VERSION 5.8 ;
BUSBITCHARS "[]" ;
DIVIDERCHAR "/" ;
UNITS
    DATABASE MICRONS 1000 ;
END UNITS

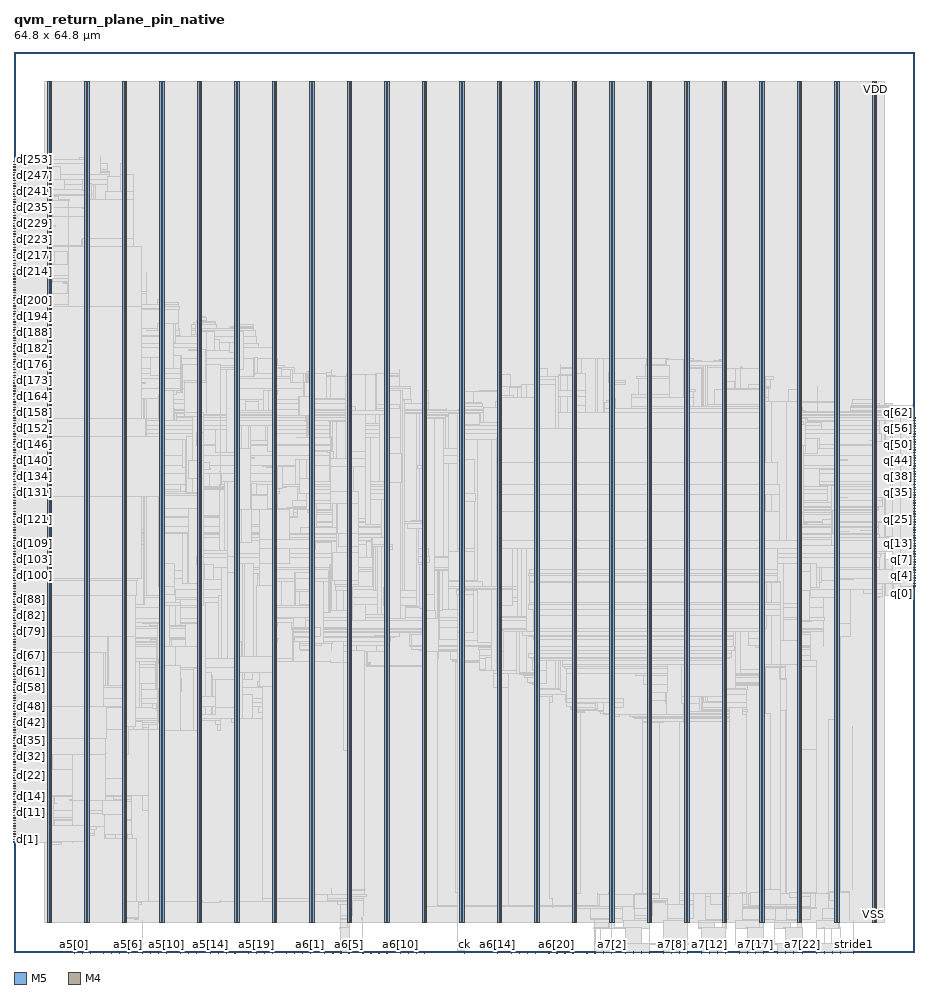
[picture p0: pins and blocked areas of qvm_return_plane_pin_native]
MACRO qvm_return_plane_pin_native
  FOREIGN qvm_return_plane_pin_native 0 0 ;
  CLASS BLOCK ;
  SIZE 64.8 BY 64.8 ;
  PIN a5[0]
    DIRECTION INPUT ;
    USE SIGNAL ;
    PORT
      LAYER M5 ;
        RECT  4.32 -0.072 4.344 0.072 ;
    END
  END a5[0]
  PIN a5[10]
    DIRECTION INPUT ;
    USE SIGNAL ;
    PORT
      LAYER M5 ;
        RECT  10.944 -0.072 10.968 0.072 ;
    END
  END a5[10]
  PIN a5[11]
    DIRECTION INPUT ;
    USE SIGNAL ;
    PORT
      LAYER M5 ;
        RECT  11.952 -0.072 11.976 0.072 ;
    END
  END a5[11]
  PIN a5[12]
    DIRECTION INPUT ;
    USE SIGNAL ;
    PORT
      LAYER M5 ;
        RECT  12.528 -0.072 12.552 0.072 ;
    END
  END a5[12]
  PIN a5[13]
    DIRECTION INPUT ;
    USE SIGNAL ;
    PORT
      LAYER M5 ;
        RECT  13.104 -0.072 13.128 0.072 ;
    END
  END a5[13]
  PIN a5[14]
    DIRECTION INPUT ;
    USE SIGNAL ;
    PORT
      LAYER M5 ;
        RECT  14.112 -0.072 14.136 0.072 ;
    END
  END a5[14]
  PIN a5[15]
    DIRECTION INPUT ;
    USE SIGNAL ;
    PORT
      LAYER M5 ;
        RECT  14.688 -0.072 14.712 0.072 ;
    END
  END a5[15]
  PIN a5[16]
    DIRECTION INPUT ;
    USE SIGNAL ;
    PORT
      LAYER M5 ;
        RECT  15.264 -0.072 15.288 0.072 ;
    END
  END a5[16]
  PIN a5[17]
    DIRECTION INPUT ;
    USE SIGNAL ;
    PORT
      LAYER M5 ;
        RECT  15.888 -0.072 15.912 0.072 ;
    END
  END a5[17]
  PIN a5[18]
    DIRECTION INPUT ;
    USE SIGNAL ;
    PORT
      LAYER M5 ;
        RECT  16.848 -0.072 16.872 0.072 ;
    END
  END a5[18]
  PIN a5[19]
    DIRECTION INPUT ;
    USE SIGNAL ;
    PORT
      LAYER M5 ;
        RECT  17.424 -0.072 17.448 0.072 ;
    END
  END a5[19]
  PIN a5[1]
    DIRECTION INPUT ;
    USE SIGNAL ;
    PORT
      LAYER M5 ;
        RECT  4.896 -0.072 4.92 0.072 ;
    END
  END a5[1]
  PIN a5[20]
    DIRECTION INPUT ;
    USE SIGNAL ;
    PORT
      LAYER M5 ;
        RECT  18 -0.072 18.024 0.072 ;
    END
  END a5[20]
  PIN a5[21]
    DIRECTION INPUT ;
    USE SIGNAL ;
    PORT
      LAYER M5 ;
        RECT  18.576 -0.072 18.6 0.072 ;
    END
  END a5[21]
  PIN a5[22]
    DIRECTION INPUT ;
    USE SIGNAL ;
    PORT
      LAYER M5 ;
        RECT  19.584 -0.072 19.608 0.072 ;
    END
  END a5[22]
  PIN a5[23]
    DIRECTION INPUT ;
    USE SIGNAL ;
    PORT
      LAYER M5 ;
        RECT  20.16 -0.072 20.184 0.072 ;
    END
  END a5[23]
  PIN a5[2]
    DIRECTION INPUT ;
    USE SIGNAL ;
    PORT
      LAYER M5 ;
        RECT  5.472 -0.072 5.496 0.072 ;
    END
  END a5[2]
  PIN a5[3]
    DIRECTION INPUT ;
    USE SIGNAL ;
    PORT
      LAYER M5 ;
        RECT  6.432 -0.072 6.456 0.072 ;
    END
  END a5[3]
  PIN a5[4]
    DIRECTION INPUT ;
    USE SIGNAL ;
    PORT
      LAYER M5 ;
        RECT  7.008 -0.072 7.032 0.072 ;
    END
  END a5[4]
  PIN a5[5]
    DIRECTION INPUT ;
    USE SIGNAL ;
    PORT
      LAYER M5 ;
        RECT  7.584 -0.072 7.608 0.072 ;
    END
  END a5[5]
  PIN a5[6]
    DIRECTION INPUT ;
    USE SIGNAL ;
    PORT
      LAYER M5 ;
        RECT  8.208 -0.072 8.232 0.072 ;
    END
  END a5[6]
  PIN a5[7]
    DIRECTION INPUT ;
    USE SIGNAL ;
    PORT
      LAYER M5 ;
        RECT  9.216 -0.072 9.24 0.072 ;
    END
  END a5[7]
  PIN a5[8]
    DIRECTION INPUT ;
    USE SIGNAL ;
    PORT
      LAYER M5 ;
        RECT  9.792 -0.072 9.816 0.072 ;
    END
  END a5[8]
  PIN a5[9]
    DIRECTION INPUT ;
    USE SIGNAL ;
    PORT
      LAYER M5 ;
        RECT  10.368 -0.072 10.392 0.072 ;
    END
  END a5[9]
  PIN a6[0]
    DIRECTION INPUT ;
    USE SIGNAL ;
    PORT
      LAYER M5 ;
        RECT  20.736 -0.072 20.76 0.072 ;
    END
  END a6[0]
  PIN a6[10]
    DIRECTION INPUT ;
    USE SIGNAL ;
    PORT
      LAYER M5 ;
        RECT  27.792 -0.072 27.816 0.072 ;
    END
  END a6[10]
  PIN a6[11]
    DIRECTION INPUT ;
    USE SIGNAL ;
    PORT
      LAYER M5 ;
        RECT  28.368 -0.072 28.392 0.072 ;
    END
  END a6[11]
  PIN a6[12]
    DIRECTION INPUT ;
    USE SIGNAL ;
    PORT
      LAYER M5 ;
        RECT  28.944 -0.072 28.968 0.072 ;
    END
  END a6[12]
  PIN a6[13]
    DIRECTION INPUT ;
    USE SIGNAL ;
    PORT
      LAYER M5 ;
        RECT  29.52 -0.072 29.544 0.072 ;
    END
  END a6[13]
  PIN a6[14]
    DIRECTION INPUT ;
    USE SIGNAL ;
    PORT
      LAYER M5 ;
        RECT  34.8 -0.072 34.824 0.072 ;
    END
  END a6[14]
  PIN a6[15]
    DIRECTION INPUT ;
    USE SIGNAL ;
    PORT
      LAYER M5 ;
        RECT  35.808 -0.072 35.832 0.072 ;
    END
  END a6[15]
  PIN a6[16]
    DIRECTION INPUT ;
    USE SIGNAL ;
    PORT
      LAYER M5 ;
        RECT  36.384 -0.072 36.408 0.072 ;
    END
  END a6[16]
  PIN a6[17]
    DIRECTION INPUT ;
    USE SIGNAL ;
    PORT
      LAYER M5 ;
        RECT  36.96 -0.072 36.984 0.072 ;
    END
  END a6[17]
  PIN a6[18]
    DIRECTION INPUT ;
    USE SIGNAL ;
    PORT
      LAYER M5 ;
        RECT  37.536 -0.072 37.56 0.072 ;
    END
  END a6[18]
  PIN a6[19]
    DIRECTION INPUT ;
    USE SIGNAL ;
    PORT
      LAYER M5 ;
        RECT  38.496 -0.072 38.52 0.072 ;
    END
  END a6[19]
  PIN a6[1]
    DIRECTION INPUT ;
    USE SIGNAL ;
    PORT
      LAYER M5 ;
        RECT  21.312 -0.072 21.336 0.072 ;
    END
  END a6[1]
  PIN a6[20]
    DIRECTION INPUT ;
    USE SIGNAL ;
    PORT
      LAYER M5 ;
        RECT  39.072 -0.072 39.096 0.072 ;
    END
  END a6[20]
  PIN a6[21]
    DIRECTION INPUT ;
    USE SIGNAL ;
    PORT
      LAYER M5 ;
        RECT  39.648 -0.072 39.672 0.072 ;
    END
  END a6[21]
  PIN a6[22]
    DIRECTION INPUT ;
    USE SIGNAL ;
    PORT
      LAYER M5 ;
        RECT  40.224 -0.072 40.248 0.072 ;
    END
  END a6[22]
  PIN a6[23]
    DIRECTION INPUT ;
    USE SIGNAL ;
    PORT
      LAYER M5 ;
        RECT  41.232 -0.072 41.256 0.072 ;
    END
  END a6[23]
  PIN a6[2]
    DIRECTION INPUT ;
    USE SIGNAL ;
    PORT
      LAYER M5 ;
        RECT  22.32 -0.072 22.344 0.072 ;
    END
  END a6[2]
  PIN a6[3]
    DIRECTION INPUT ;
    USE SIGNAL ;
    PORT
      LAYER M5 ;
        RECT  22.944 -0.072 22.968 0.072 ;
    END
  END a6[3]
  PIN a6[4]
    DIRECTION INPUT ;
    USE SIGNAL ;
    PORT
      LAYER M5 ;
        RECT  23.52 -0.072 23.544 0.072 ;
    END
  END a6[4]
  PIN a6[5]
    DIRECTION INPUT ;
    USE SIGNAL ;
    PORT
      LAYER M5 ;
        RECT  24.096 -0.072 24.12 0.072 ;
    END
  END a6[5]
  PIN a6[6]
    DIRECTION INPUT ;
    USE SIGNAL ;
    PORT
      LAYER M5 ;
        RECT  25.104 -0.072 25.128 0.072 ;
    END
  END a6[6]
  PIN a6[7]
    DIRECTION INPUT ;
    USE SIGNAL ;
    PORT
      LAYER M5 ;
        RECT  25.68 -0.072 25.704 0.072 ;
    END
  END a6[7]
  PIN a6[8]
    DIRECTION INPUT ;
    USE SIGNAL ;
    PORT
      LAYER M5 ;
        RECT  26.256 -0.072 26.28 0.072 ;
    END
  END a6[8]
  PIN a6[9]
    DIRECTION INPUT ;
    USE SIGNAL ;
    PORT
      LAYER M5 ;
        RECT  26.832 -0.072 26.856 0.072 ;
    END
  END a6[9]
  PIN a7[0]
    DIRECTION INPUT ;
    USE SIGNAL ;
    PORT
      LAYER M5 ;
        RECT  41.808 -0.072 41.832 0.072 ;
    END
  END a7[0]
  PIN a7[10]
    DIRECTION INPUT ;
    USE SIGNAL ;
    PORT
      LAYER M5 ;
        RECT  48.48 -0.072 48.504 0.072 ;
    END
  END a7[10]
  PIN a7[11]
    DIRECTION INPUT ;
    USE SIGNAL ;
    PORT
      LAYER M5 ;
        RECT  49.488 -0.072 49.512 0.072 ;
    END
  END a7[11]
  PIN a7[12]
    DIRECTION INPUT ;
    USE SIGNAL ;
    PORT
      LAYER M5 ;
        RECT  50.064 -0.072 50.088 0.072 ;
    END
  END a7[12]
  PIN a7[13]
    DIRECTION INPUT ;
    USE SIGNAL ;
    PORT
      LAYER M5 ;
        RECT  50.64 -0.072 50.664 0.072 ;
    END
  END a7[13]
  PIN a7[14]
    DIRECTION INPUT ;
    USE SIGNAL ;
    PORT
      LAYER M5 ;
        RECT  51.216 -0.072 51.24 0.072 ;
    END
  END a7[14]
  PIN a7[15]
    DIRECTION INPUT ;
    USE SIGNAL ;
    PORT
      LAYER M5 ;
        RECT  52.224 -0.072 52.248 0.072 ;
    END
  END a7[15]
  PIN a7[16]
    DIRECTION INPUT ;
    USE SIGNAL ;
    PORT
      LAYER M5 ;
        RECT  52.8 -0.072 52.824 0.072 ;
    END
  END a7[16]
  PIN a7[17]
    DIRECTION INPUT ;
    USE SIGNAL ;
    PORT
      LAYER M5 ;
        RECT  53.376 -0.072 53.4 0.072 ;
    END
  END a7[17]
  PIN a7[18]
    DIRECTION INPUT ;
    USE SIGNAL ;
    PORT
      LAYER M5 ;
        RECT  53.952 -0.072 53.976 0.072 ;
    END
  END a7[18]
  PIN a7[19]
    DIRECTION INPUT ;
    USE SIGNAL ;
    PORT
      LAYER M5 ;
        RECT  54.96 -0.072 54.984 0.072 ;
    END
  END a7[19]
  PIN a7[1]
    DIRECTION INPUT ;
    USE SIGNAL ;
    PORT
      LAYER M5 ;
        RECT  42.432 -0.072 42.456 0.072 ;
    END
  END a7[1]
  PIN a7[20]
    DIRECTION INPUT ;
    USE SIGNAL ;
    PORT
      LAYER M5 ;
        RECT  55.536 -0.072 55.56 0.072 ;
    END
  END a7[20]
  PIN a7[21]
    DIRECTION INPUT ;
    USE SIGNAL ;
    PORT
      LAYER M5 ;
        RECT  56.112 -0.072 56.136 0.072 ;
    END
  END a7[21]
  PIN a7[22]
    DIRECTION INPUT ;
    USE SIGNAL ;
    PORT
      LAYER M5 ;
        RECT  56.736 -0.072 56.76 0.072 ;
    END
  END a7[22]
  PIN a7[23]
    DIRECTION INPUT ;
    USE SIGNAL ;
    PORT
      LAYER M5 ;
        RECT  57.744 -0.072 57.768 0.072 ;
    END
  END a7[23]
  PIN a7[2]
    DIRECTION INPUT ;
    USE SIGNAL ;
    PORT
      LAYER M5 ;
        RECT  43.008 -0.072 43.032 0.072 ;
    END
  END a7[2]
  PIN a7[3]
    DIRECTION INPUT ;
    USE SIGNAL ;
    PORT
      LAYER M5 ;
        RECT  44.016 -0.072 44.04 0.072 ;
    END
  END a7[3]
  PIN a7[4]
    DIRECTION INPUT ;
    USE SIGNAL ;
    PORT
      LAYER M5 ;
        RECT  44.592 -0.072 44.616 0.072 ;
    END
  END a7[4]
  PIN a7[5]
    DIRECTION INPUT ;
    USE SIGNAL ;
    PORT
      LAYER M5 ;
        RECT  45.168 -0.072 45.192 0.072 ;
    END
  END a7[5]
  PIN a7[6]
    DIRECTION INPUT ;
    USE SIGNAL ;
    PORT
      LAYER M5 ;
        RECT  45.744 -0.072 45.768 0.072 ;
    END
  END a7[6]
  PIN a7[7]
    DIRECTION INPUT ;
    USE SIGNAL ;
    PORT
      LAYER M5 ;
        RECT  46.752 -0.072 46.776 0.072 ;
    END
  END a7[7]
  PIN a7[8]
    DIRECTION INPUT ;
    USE SIGNAL ;
    PORT
      LAYER M5 ;
        RECT  47.328 -0.072 47.352 0.072 ;
    END
  END a7[8]
  PIN a7[9]
    DIRECTION INPUT ;
    USE SIGNAL ;
    PORT
      LAYER M5 ;
        RECT  47.904 -0.072 47.928 0.072 ;
    END
  END a7[9]
  PIN ck
    DIRECTION INPUT ;
    USE SIGNAL ;
    PORT
      LAYER M5 ;
        RECT  32.4 -0.072 32.424 0.072 ;
    END
  END ck
  PIN d[0]
    DIRECTION INPUT ;
    USE SIGNAL ;
    PORT
      LAYER M4 ;
        RECT  -0.072 7.92 0.072 7.944 ;
    END
  END d[0]
  PIN d[100]
    DIRECTION INPUT ;
    USE SIGNAL ;
    PORT
      LAYER M4 ;
        RECT  -0.072 27.12 0.072 27.144 ;
    END
  END d[100]
  PIN d[101]
    DIRECTION INPUT ;
    USE SIGNAL ;
    PORT
      LAYER M4 ;
        RECT  -0.072 27.312 0.072 27.336 ;
    END
  END d[101]
  PIN d[102]
    DIRECTION INPUT ;
    USE SIGNAL ;
    PORT
      LAYER M4 ;
        RECT  -0.072 27.504 0.072 27.528 ;
    END
  END d[102]
  PIN d[103]
    DIRECTION INPUT ;
    USE SIGNAL ;
    PORT
      LAYER M4 ;
        RECT  -0.072 27.696 0.072 27.72 ;
    END
  END d[103]
  PIN d[104]
    DIRECTION INPUT ;
    USE SIGNAL ;
    PORT
      LAYER M4 ;
        RECT  -0.072 27.888 0.072 27.912 ;
    END
  END d[104]
  PIN d[105]
    DIRECTION INPUT ;
    USE SIGNAL ;
    PORT
      LAYER M4 ;
        RECT  -0.072 28.08 0.072 28.104 ;
    END
  END d[105]
  PIN d[106]
    DIRECTION INPUT ;
    USE SIGNAL ;
    PORT
      LAYER M4 ;
        RECT  -0.072 28.272 0.072 28.296 ;
    END
  END d[106]
  PIN d[107]
    DIRECTION INPUT ;
    USE SIGNAL ;
    PORT
      LAYER M4 ;
        RECT  -0.072 28.464 0.072 28.488 ;
    END
  END d[107]
  PIN d[108]
    DIRECTION INPUT ;
    USE SIGNAL ;
    PORT
      LAYER M4 ;
        RECT  -0.072 28.656 0.072 28.68 ;
    END
  END d[108]
  PIN d[109]
    DIRECTION INPUT ;
    USE SIGNAL ;
    PORT
      LAYER M4 ;
        RECT  -0.072 28.848 0.072 28.872 ;
    END
  END d[109]
  PIN d[10]
    DIRECTION INPUT ;
    USE SIGNAL ;
    PORT
      LAYER M4 ;
        RECT  -0.072 9.84 0.072 9.864 ;
    END
  END d[10]
  PIN d[110]
    DIRECTION INPUT ;
    USE SIGNAL ;
    PORT
      LAYER M4 ;
        RECT  -0.072 29.04 0.072 29.064 ;
    END
  END d[110]
  PIN d[111]
    DIRECTION INPUT ;
    USE SIGNAL ;
    PORT
      LAYER M4 ;
        RECT  -0.072 29.232 0.072 29.256 ;
    END
  END d[111]
  PIN d[112]
    DIRECTION INPUT ;
    USE SIGNAL ;
    PORT
      LAYER M4 ;
        RECT  -0.072 29.424 0.072 29.448 ;
    END
  END d[112]
  PIN d[113]
    DIRECTION INPUT ;
    USE SIGNAL ;
    PORT
      LAYER M4 ;
        RECT  -0.072 29.616 0.072 29.64 ;
    END
  END d[113]
  PIN d[114]
    DIRECTION INPUT ;
    USE SIGNAL ;
    PORT
      LAYER M4 ;
        RECT  -0.072 29.808 0.072 29.832 ;
    END
  END d[114]
  PIN d[115]
    DIRECTION INPUT ;
    USE SIGNAL ;
    PORT
      LAYER M4 ;
        RECT  -0.072 30 0.072 30.024 ;
    END
  END d[115]
  PIN d[116]
    DIRECTION INPUT ;
    USE SIGNAL ;
    PORT
      LAYER M4 ;
        RECT  -0.072 30.192 0.072 30.216 ;
    END
  END d[116]
  PIN d[117]
    DIRECTION INPUT ;
    USE SIGNAL ;
    PORT
      LAYER M4 ;
        RECT  -0.072 30.384 0.072 30.408 ;
    END
  END d[117]
  PIN d[118]
    DIRECTION INPUT ;
    USE SIGNAL ;
    PORT
      LAYER M4 ;
        RECT  -0.072 30.576 0.072 30.6 ;
    END
  END d[118]
  PIN d[119]
    DIRECTION INPUT ;
    USE SIGNAL ;
    PORT
      LAYER M4 ;
        RECT  -0.072 30.768 0.072 30.792 ;
    END
  END d[119]
  PIN d[11]
    DIRECTION INPUT ;
    USE SIGNAL ;
    PORT
      LAYER M4 ;
        RECT  -0.072 10.032 0.072 10.056 ;
    END
  END d[11]
  PIN d[120]
    DIRECTION INPUT ;
    USE SIGNAL ;
    PORT
      LAYER M4 ;
        RECT  -0.072 30.96 0.072 30.984 ;
    END
  END d[120]
  PIN d[121]
    DIRECTION INPUT ;
    USE SIGNAL ;
    PORT
      LAYER M4 ;
        RECT  -0.072 31.152 0.072 31.176 ;
    END
  END d[121]
  PIN d[122]
    DIRECTION INPUT ;
    USE SIGNAL ;
    PORT
      LAYER M4 ;
        RECT  -0.072 31.344 0.072 31.368 ;
    END
  END d[122]
  PIN d[123]
    DIRECTION INPUT ;
    USE SIGNAL ;
    PORT
      LAYER M4 ;
        RECT  -0.072 31.536 0.072 31.56 ;
    END
  END d[123]
  PIN d[124]
    DIRECTION INPUT ;
    USE SIGNAL ;
    PORT
      LAYER M4 ;
        RECT  -0.072 31.728 0.072 31.752 ;
    END
  END d[124]
  PIN d[125]
    DIRECTION INPUT ;
    USE SIGNAL ;
    PORT
      LAYER M4 ;
        RECT  -0.072 31.92 0.072 31.944 ;
    END
  END d[125]
  PIN d[126]
    DIRECTION INPUT ;
    USE SIGNAL ;
    PORT
      LAYER M4 ;
        RECT  -0.072 32.112 0.072 32.136 ;
    END
  END d[126]
  PIN d[127]
    DIRECTION INPUT ;
    USE SIGNAL ;
    PORT
      LAYER M4 ;
        RECT  -0.072 32.304 0.072 32.328 ;
    END
  END d[127]
  PIN d[128]
    DIRECTION INPUT ;
    USE SIGNAL ;
    PORT
      LAYER M4 ;
        RECT  -0.072 32.496 0.072 32.52 ;
    END
  END d[128]
  PIN d[129]
    DIRECTION INPUT ;
    USE SIGNAL ;
    PORT
      LAYER M4 ;
        RECT  -0.072 32.688 0.072 32.712 ;
    END
  END d[129]
  PIN d[12]
    DIRECTION INPUT ;
    USE SIGNAL ;
    PORT
      LAYER M4 ;
        RECT  -0.072 10.224 0.072 10.248 ;
    END
  END d[12]
  PIN d[130]
    DIRECTION INPUT ;
    USE SIGNAL ;
    PORT
      LAYER M4 ;
        RECT  -0.072 32.88 0.072 32.904 ;
    END
  END d[130]
  PIN d[131]
    DIRECTION INPUT ;
    USE SIGNAL ;
    PORT
      LAYER M4 ;
        RECT  -0.072 33.072 0.072 33.096 ;
    END
  END d[131]
  PIN d[132]
    DIRECTION INPUT ;
    USE SIGNAL ;
    PORT
      LAYER M4 ;
        RECT  -0.072 33.264 0.072 33.288 ;
    END
  END d[132]
  PIN d[133]
    DIRECTION INPUT ;
    USE SIGNAL ;
    PORT
      LAYER M4 ;
        RECT  -0.072 33.456 0.072 33.48 ;
    END
  END d[133]
  PIN d[134]
    DIRECTION INPUT ;
    USE SIGNAL ;
    PORT
      LAYER M4 ;
        RECT  -0.072 33.648 0.072 33.672 ;
    END
  END d[134]
  PIN d[135]
    DIRECTION INPUT ;
    USE SIGNAL ;
    PORT
      LAYER M4 ;
        RECT  -0.072 33.84 0.072 33.864 ;
    END
  END d[135]
  PIN d[136]
    DIRECTION INPUT ;
    USE SIGNAL ;
    PORT
      LAYER M4 ;
        RECT  -0.072 34.032 0.072 34.056 ;
    END
  END d[136]
  PIN d[137]
    DIRECTION INPUT ;
    USE SIGNAL ;
    PORT
      LAYER M4 ;
        RECT  -0.072 34.224 0.072 34.248 ;
    END
  END d[137]
  PIN d[138]
    DIRECTION INPUT ;
    USE SIGNAL ;
    PORT
      LAYER M4 ;
        RECT  -0.072 34.416 0.072 34.44 ;
    END
  END d[138]
  PIN d[139]
    DIRECTION INPUT ;
    USE SIGNAL ;
    PORT
      LAYER M4 ;
        RECT  -0.072 34.608 0.072 34.632 ;
    END
  END d[139]
  PIN d[13]
    DIRECTION INPUT ;
    USE SIGNAL ;
    PORT
      LAYER M4 ;
        RECT  -0.072 10.416 0.072 10.44 ;
    END
  END d[13]
  PIN d[140]
    DIRECTION INPUT ;
    USE SIGNAL ;
    PORT
      LAYER M4 ;
        RECT  -0.072 34.8 0.072 34.824 ;
    END
  END d[140]
  PIN d[141]
    DIRECTION INPUT ;
    USE SIGNAL ;
    PORT
      LAYER M4 ;
        RECT  -0.072 34.992 0.072 35.016 ;
    END
  END d[141]
  PIN d[142]
    DIRECTION INPUT ;
    USE SIGNAL ;
    PORT
      LAYER M4 ;
        RECT  -0.072 35.184 0.072 35.208 ;
    END
  END d[142]
  PIN d[143]
    DIRECTION INPUT ;
    USE SIGNAL ;
    PORT
      LAYER M4 ;
        RECT  -0.072 35.376 0.072 35.4 ;
    END
  END d[143]
  PIN d[144]
    DIRECTION INPUT ;
    USE SIGNAL ;
    PORT
      LAYER M4 ;
        RECT  -0.072 35.568 0.072 35.592 ;
    END
  END d[144]
  PIN d[145]
    DIRECTION INPUT ;
    USE SIGNAL ;
    PORT
      LAYER M4 ;
        RECT  -0.072 35.76 0.072 35.784 ;
    END
  END d[145]
  PIN d[146]
    DIRECTION INPUT ;
    USE SIGNAL ;
    PORT
      LAYER M4 ;
        RECT  -0.072 35.952 0.072 35.976 ;
    END
  END d[146]
  PIN d[147]
    DIRECTION INPUT ;
    USE SIGNAL ;
    PORT
      LAYER M4 ;
        RECT  -0.072 36.144 0.072 36.168 ;
    END
  END d[147]
  PIN d[148]
    DIRECTION INPUT ;
    USE SIGNAL ;
    PORT
      LAYER M4 ;
        RECT  -0.072 36.336 0.072 36.36 ;
    END
  END d[148]
  PIN d[149]
    DIRECTION INPUT ;
    USE SIGNAL ;
    PORT
      LAYER M4 ;
        RECT  -0.072 36.528 0.072 36.552 ;
    END
  END d[149]
  PIN d[14]
    DIRECTION INPUT ;
    USE SIGNAL ;
    PORT
      LAYER M4 ;
        RECT  -0.072 10.608 0.072 10.632 ;
    END
  END d[14]
  PIN d[150]
    DIRECTION INPUT ;
    USE SIGNAL ;
    PORT
      LAYER M4 ;
        RECT  -0.072 36.72 0.072 36.744 ;
    END
  END d[150]
  PIN d[151]
    DIRECTION INPUT ;
    USE SIGNAL ;
    PORT
      LAYER M4 ;
        RECT  -0.072 36.912 0.072 36.936 ;
    END
  END d[151]
  PIN d[152]
    DIRECTION INPUT ;
    USE SIGNAL ;
    PORT
      LAYER M4 ;
        RECT  -0.072 37.104 0.072 37.128 ;
    END
  END d[152]
  PIN d[153]
    DIRECTION INPUT ;
    USE SIGNAL ;
    PORT
      LAYER M4 ;
        RECT  -0.072 37.296 0.072 37.32 ;
    END
  END d[153]
  PIN d[154]
    DIRECTION INPUT ;
    USE SIGNAL ;
    PORT
      LAYER M4 ;
        RECT  -0.072 37.488 0.072 37.512 ;
    END
  END d[154]
  PIN d[155]
    DIRECTION INPUT ;
    USE SIGNAL ;
    PORT
      LAYER M4 ;
        RECT  -0.072 37.68 0.072 37.704 ;
    END
  END d[155]
  PIN d[156]
    DIRECTION INPUT ;
    USE SIGNAL ;
    PORT
      LAYER M4 ;
        RECT  -0.072 37.872 0.072 37.896 ;
    END
  END d[156]
  PIN d[157]
    DIRECTION INPUT ;
    USE SIGNAL ;
    PORT
      LAYER M4 ;
        RECT  -0.072 38.064 0.072 38.088 ;
    END
  END d[157]
  PIN d[158]
    DIRECTION INPUT ;
    USE SIGNAL ;
    PORT
      LAYER M4 ;
        RECT  -0.072 38.256 0.072 38.28 ;
    END
  END d[158]
  PIN d[159]
    DIRECTION INPUT ;
    USE SIGNAL ;
    PORT
      LAYER M4 ;
        RECT  -0.072 38.448 0.072 38.472 ;
    END
  END d[159]
  PIN d[15]
    DIRECTION INPUT ;
    USE SIGNAL ;
    PORT
      LAYER M4 ;
        RECT  -0.072 10.8 0.072 10.824 ;
    END
  END d[15]
  PIN d[160]
    DIRECTION INPUT ;
    USE SIGNAL ;
    PORT
      LAYER M4 ;
        RECT  -0.072 38.64 0.072 38.664 ;
    END
  END d[160]
  PIN d[161]
    DIRECTION INPUT ;
    USE SIGNAL ;
    PORT
      LAYER M4 ;
        RECT  -0.072 38.832 0.072 38.856 ;
    END
  END d[161]
  PIN d[162]
    DIRECTION INPUT ;
    USE SIGNAL ;
    PORT
      LAYER M4 ;
        RECT  -0.072 39.024 0.072 39.048 ;
    END
  END d[162]
  PIN d[163]
    DIRECTION INPUT ;
    USE SIGNAL ;
    PORT
      LAYER M4 ;
        RECT  -0.072 39.216 0.072 39.24 ;
    END
  END d[163]
  PIN d[164]
    DIRECTION INPUT ;
    USE SIGNAL ;
    PORT
      LAYER M4 ;
        RECT  -0.072 39.408 0.072 39.432 ;
    END
  END d[164]
  PIN d[165]
    DIRECTION INPUT ;
    USE SIGNAL ;
    PORT
      LAYER M4 ;
        RECT  -0.072 39.6 0.072 39.624 ;
    END
  END d[165]
  PIN d[166]
    DIRECTION INPUT ;
    USE SIGNAL ;
    PORT
      LAYER M4 ;
        RECT  -0.072 39.792 0.072 39.816 ;
    END
  END d[166]
  PIN d[167]
    DIRECTION INPUT ;
    USE SIGNAL ;
    PORT
      LAYER M4 ;
        RECT  -0.072 39.984 0.072 40.008 ;
    END
  END d[167]
  PIN d[168]
    DIRECTION INPUT ;
    USE SIGNAL ;
    PORT
      LAYER M4 ;
        RECT  -0.072 40.176 0.072 40.2 ;
    END
  END d[168]
  PIN d[169]
    DIRECTION INPUT ;
    USE SIGNAL ;
    PORT
      LAYER M4 ;
        RECT  -0.072 40.368 0.072 40.392 ;
    END
  END d[169]
  PIN d[16]
    DIRECTION INPUT ;
    USE SIGNAL ;
    PORT
      LAYER M4 ;
        RECT  -0.072 10.992 0.072 11.016 ;
    END
  END d[16]
  PIN d[170]
    DIRECTION INPUT ;
    USE SIGNAL ;
    PORT
      LAYER M4 ;
        RECT  -0.072 40.56 0.072 40.584 ;
    END
  END d[170]
  PIN d[171]
    DIRECTION INPUT ;
    USE SIGNAL ;
    PORT
      LAYER M4 ;
        RECT  -0.072 40.752 0.072 40.776 ;
    END
  END d[171]
  PIN d[172]
    DIRECTION INPUT ;
    USE SIGNAL ;
    PORT
      LAYER M4 ;
        RECT  -0.072 40.944 0.072 40.968 ;
    END
  END d[172]
  PIN d[173]
    DIRECTION INPUT ;
    USE SIGNAL ;
    PORT
      LAYER M4 ;
        RECT  -0.072 41.136 0.072 41.16 ;
    END
  END d[173]
  PIN d[174]
    DIRECTION INPUT ;
    USE SIGNAL ;
    PORT
      LAYER M4 ;
        RECT  -0.072 41.328 0.072 41.352 ;
    END
  END d[174]
  PIN d[175]
    DIRECTION INPUT ;
    USE SIGNAL ;
    PORT
      LAYER M4 ;
        RECT  -0.072 41.52 0.072 41.544 ;
    END
  END d[175]
  PIN d[176]
    DIRECTION INPUT ;
    USE SIGNAL ;
    PORT
      LAYER M4 ;
        RECT  -0.072 41.712 0.072 41.736 ;
    END
  END d[176]
  PIN d[177]
    DIRECTION INPUT ;
    USE SIGNAL ;
    PORT
      LAYER M4 ;
        RECT  -0.072 41.904 0.072 41.928 ;
    END
  END d[177]
  PIN d[178]
    DIRECTION INPUT ;
    USE SIGNAL ;
    PORT
      LAYER M4 ;
        RECT  -0.072 42.096 0.072 42.12 ;
    END
  END d[178]
  PIN d[179]
    DIRECTION INPUT ;
    USE SIGNAL ;
    PORT
      LAYER M4 ;
        RECT  -0.072 42.288 0.072 42.312 ;
    END
  END d[179]
  PIN d[17]
    DIRECTION INPUT ;
    USE SIGNAL ;
    PORT
      LAYER M4 ;
        RECT  -0.072 11.184 0.072 11.208 ;
    END
  END d[17]
  PIN d[180]
    DIRECTION INPUT ;
    USE SIGNAL ;
    PORT
      LAYER M4 ;
        RECT  -0.072 42.48 0.072 42.504 ;
    END
  END d[180]
  PIN d[181]
    DIRECTION INPUT ;
    USE SIGNAL ;
    PORT
      LAYER M4 ;
        RECT  -0.072 42.672 0.072 42.696 ;
    END
  END d[181]
  PIN d[182]
    DIRECTION INPUT ;
    USE SIGNAL ;
    PORT
      LAYER M4 ;
        RECT  -0.072 42.864 0.072 42.888 ;
    END
  END d[182]
  PIN d[183]
    DIRECTION INPUT ;
    USE SIGNAL ;
    PORT
      LAYER M4 ;
        RECT  -0.072 43.056 0.072 43.08 ;
    END
  END d[183]
  PIN d[184]
    DIRECTION INPUT ;
    USE SIGNAL ;
    PORT
      LAYER M4 ;
        RECT  -0.072 43.248 0.072 43.272 ;
    END
  END d[184]
  PIN d[185]
    DIRECTION INPUT ;
    USE SIGNAL ;
    PORT
      LAYER M4 ;
        RECT  -0.072 43.44 0.072 43.464 ;
    END
  END d[185]
  PIN d[186]
    DIRECTION INPUT ;
    USE SIGNAL ;
    PORT
      LAYER M4 ;
        RECT  -0.072 43.632 0.072 43.656 ;
    END
  END d[186]
  PIN d[187]
    DIRECTION INPUT ;
    USE SIGNAL ;
    PORT
      LAYER M4 ;
        RECT  -0.072 43.824 0.072 43.848 ;
    END
  END d[187]
  PIN d[188]
    DIRECTION INPUT ;
    USE SIGNAL ;
    PORT
      LAYER M4 ;
        RECT  -0.072 44.016 0.072 44.04 ;
    END
  END d[188]
  PIN d[189]
    DIRECTION INPUT ;
    USE SIGNAL ;
    PORT
      LAYER M4 ;
        RECT  -0.072 44.208 0.072 44.232 ;
    END
  END d[189]
  PIN d[18]
    DIRECTION INPUT ;
    USE SIGNAL ;
    PORT
      LAYER M4 ;
        RECT  -0.072 11.376 0.072 11.4 ;
    END
  END d[18]
  PIN d[190]
    DIRECTION INPUT ;
    USE SIGNAL ;
    PORT
      LAYER M4 ;
        RECT  -0.072 44.4 0.072 44.424 ;
    END
  END d[190]
  PIN d[191]
    DIRECTION INPUT ;
    USE SIGNAL ;
    PORT
      LAYER M4 ;
        RECT  -0.072 44.592 0.072 44.616 ;
    END
  END d[191]
  PIN d[192]
    DIRECTION INPUT ;
    USE SIGNAL ;
    PORT
      LAYER M4 ;
        RECT  -0.072 44.784 0.072 44.808 ;
    END
  END d[192]
  PIN d[193]
    DIRECTION INPUT ;
    USE SIGNAL ;
    PORT
      LAYER M4 ;
        RECT  -0.072 44.976 0.072 45 ;
    END
  END d[193]
  PIN d[194]
    DIRECTION INPUT ;
    USE SIGNAL ;
    PORT
      LAYER M4 ;
        RECT  -0.072 45.168 0.072 45.192 ;
    END
  END d[194]
  PIN d[195]
    DIRECTION INPUT ;
    USE SIGNAL ;
    PORT
      LAYER M4 ;
        RECT  -0.072 45.36 0.072 45.384 ;
    END
  END d[195]
  PIN d[196]
    DIRECTION INPUT ;
    USE SIGNAL ;
    PORT
      LAYER M4 ;
        RECT  -0.072 45.552 0.072 45.576 ;
    END
  END d[196]
  PIN d[197]
    DIRECTION INPUT ;
    USE SIGNAL ;
    PORT
      LAYER M4 ;
        RECT  -0.072 45.744 0.072 45.768 ;
    END
  END d[197]
  PIN d[198]
    DIRECTION INPUT ;
    USE SIGNAL ;
    PORT
      LAYER M4 ;
        RECT  -0.072 45.936 0.072 45.96 ;
    END
  END d[198]
  PIN d[199]
    DIRECTION INPUT ;
    USE SIGNAL ;
    PORT
      LAYER M4 ;
        RECT  -0.072 46.128 0.072 46.152 ;
    END
  END d[199]
  PIN d[19]
    DIRECTION INPUT ;
    USE SIGNAL ;
    PORT
      LAYER M4 ;
        RECT  -0.072 11.568 0.072 11.592 ;
    END
  END d[19]
  PIN d[1]
    DIRECTION INPUT ;
    USE SIGNAL ;
    PORT
      LAYER M4 ;
        RECT  -0.072 8.112 0.072 8.136 ;
    END
  END d[1]
  PIN d[200]
    DIRECTION INPUT ;
    USE SIGNAL ;
    PORT
      LAYER M4 ;
        RECT  -0.072 46.32 0.072 46.344 ;
    END
  END d[200]
  PIN d[201]
    DIRECTION INPUT ;
    USE SIGNAL ;
    PORT
      LAYER M4 ;
        RECT  -0.072 46.512 0.072 46.536 ;
    END
  END d[201]
  PIN d[202]
    DIRECTION INPUT ;
    USE SIGNAL ;
    PORT
      LAYER M4 ;
        RECT  -0.072 46.704 0.072 46.728 ;
    END
  END d[202]
  PIN d[203]
    DIRECTION INPUT ;
    USE SIGNAL ;
    PORT
      LAYER M4 ;
        RECT  -0.072 46.896 0.072 46.92 ;
    END
  END d[203]
  PIN d[204]
    DIRECTION INPUT ;
    USE SIGNAL ;
    PORT
      LAYER M4 ;
        RECT  -0.072 47.088 0.072 47.112 ;
    END
  END d[204]
  PIN d[205]
    DIRECTION INPUT ;
    USE SIGNAL ;
    PORT
      LAYER M4 ;
        RECT  -0.072 47.28 0.072 47.304 ;
    END
  END d[205]
  PIN d[206]
    DIRECTION INPUT ;
    USE SIGNAL ;
    PORT
      LAYER M4 ;
        RECT  -0.072 47.472 0.072 47.496 ;
    END
  END d[206]
  PIN d[207]
    DIRECTION INPUT ;
    USE SIGNAL ;
    PORT
      LAYER M4 ;
        RECT  -0.072 47.664 0.072 47.688 ;
    END
  END d[207]
  PIN d[208]
    DIRECTION INPUT ;
    USE SIGNAL ;
    PORT
      LAYER M4 ;
        RECT  -0.072 47.856 0.072 47.88 ;
    END
  END d[208]
  PIN d[209]
    DIRECTION INPUT ;
    USE SIGNAL ;
    PORT
      LAYER M4 ;
        RECT  -0.072 48.048 0.072 48.072 ;
    END
  END d[209]
  PIN d[20]
    DIRECTION INPUT ;
    USE SIGNAL ;
    PORT
      LAYER M4 ;
        RECT  -0.072 11.76 0.072 11.784 ;
    END
  END d[20]
  PIN d[210]
    DIRECTION INPUT ;
    USE SIGNAL ;
    PORT
      LAYER M4 ;
        RECT  -0.072 48.24 0.072 48.264 ;
    END
  END d[210]
  PIN d[211]
    DIRECTION INPUT ;
    USE SIGNAL ;
    PORT
      LAYER M4 ;
        RECT  -0.072 48.432 0.072 48.456 ;
    END
  END d[211]
  PIN d[212]
    DIRECTION INPUT ;
    USE SIGNAL ;
    PORT
      LAYER M4 ;
        RECT  -0.072 48.624 0.072 48.648 ;
    END
  END d[212]
  PIN d[213]
    DIRECTION INPUT ;
    USE SIGNAL ;
    PORT
      LAYER M4 ;
        RECT  -0.072 48.816 0.072 48.84 ;
    END
  END d[213]
  PIN d[214]
    DIRECTION INPUT ;
    USE SIGNAL ;
    PORT
      LAYER M4 ;
        RECT  -0.072 49.008 0.072 49.032 ;
    END
  END d[214]
  PIN d[215]
    DIRECTION INPUT ;
    USE SIGNAL ;
    PORT
      LAYER M4 ;
        RECT  -0.072 49.2 0.072 49.224 ;
    END
  END d[215]
  PIN d[216]
    DIRECTION INPUT ;
    USE SIGNAL ;
    PORT
      LAYER M4 ;
        RECT  -0.072 49.392 0.072 49.416 ;
    END
  END d[216]
  PIN d[217]
    DIRECTION INPUT ;
    USE SIGNAL ;
    PORT
      LAYER M4 ;
        RECT  -0.072 49.584 0.072 49.608 ;
    END
  END d[217]
  PIN d[218]
    DIRECTION INPUT ;
    USE SIGNAL ;
    PORT
      LAYER M4 ;
        RECT  -0.072 49.776 0.072 49.8 ;
    END
  END d[218]
  PIN d[219]
    DIRECTION INPUT ;
    USE SIGNAL ;
    PORT
      LAYER M4 ;
        RECT  -0.072 49.968 0.072 49.992 ;
    END
  END d[219]
  PIN d[21]
    DIRECTION INPUT ;
    USE SIGNAL ;
    PORT
      LAYER M4 ;
        RECT  -0.072 11.952 0.072 11.976 ;
    END
  END d[21]
  PIN d[220]
    DIRECTION INPUT ;
    USE SIGNAL ;
    PORT
      LAYER M4 ;
        RECT  -0.072 50.16 0.072 50.184 ;
    END
  END d[220]
  PIN d[221]
    DIRECTION INPUT ;
    USE SIGNAL ;
    PORT
      LAYER M4 ;
        RECT  -0.072 50.352 0.072 50.376 ;
    END
  END d[221]
  PIN d[222]
    DIRECTION INPUT ;
    USE SIGNAL ;
    PORT
      LAYER M4 ;
        RECT  -0.072 50.544 0.072 50.568 ;
    END
  END d[222]
  PIN d[223]
    DIRECTION INPUT ;
    USE SIGNAL ;
    PORT
      LAYER M4 ;
        RECT  -0.072 50.736 0.072 50.76 ;
    END
  END d[223]
  PIN d[224]
    DIRECTION INPUT ;
    USE SIGNAL ;
    PORT
      LAYER M4 ;
        RECT  -0.072 50.928 0.072 50.952 ;
    END
  END d[224]
  PIN d[225]
    DIRECTION INPUT ;
    USE SIGNAL ;
    PORT
      LAYER M4 ;
        RECT  -0.072 51.12 0.072 51.144 ;
    END
  END d[225]
  PIN d[226]
    DIRECTION INPUT ;
    USE SIGNAL ;
    PORT
      LAYER M4 ;
        RECT  -0.072 51.312 0.072 51.336 ;
    END
  END d[226]
  PIN d[227]
    DIRECTION INPUT ;
    USE SIGNAL ;
    PORT
      LAYER M4 ;
        RECT  -0.072 51.504 0.072 51.528 ;
    END
  END d[227]
  PIN d[228]
    DIRECTION INPUT ;
    USE SIGNAL ;
    PORT
      LAYER M4 ;
        RECT  -0.072 51.696 0.072 51.72 ;
    END
  END d[228]
  PIN d[229]
    DIRECTION INPUT ;
    USE SIGNAL ;
    PORT
      LAYER M4 ;
        RECT  -0.072 51.888 0.072 51.912 ;
    END
  END d[229]
  PIN d[22]
    DIRECTION INPUT ;
    USE SIGNAL ;
    PORT
      LAYER M4 ;
        RECT  -0.072 12.144 0.072 12.168 ;
    END
  END d[22]
  PIN d[230]
    DIRECTION INPUT ;
    USE SIGNAL ;
    PORT
      LAYER M4 ;
        RECT  -0.072 52.08 0.072 52.104 ;
    END
  END d[230]
  PIN d[231]
    DIRECTION INPUT ;
    USE SIGNAL ;
    PORT
      LAYER M4 ;
        RECT  -0.072 52.272 0.072 52.296 ;
    END
  END d[231]
  PIN d[232]
    DIRECTION INPUT ;
    USE SIGNAL ;
    PORT
      LAYER M4 ;
        RECT  -0.072 52.464 0.072 52.488 ;
    END
  END d[232]
  PIN d[233]
    DIRECTION INPUT ;
    USE SIGNAL ;
    PORT
      LAYER M4 ;
        RECT  -0.072 52.656 0.072 52.68 ;
    END
  END d[233]
  PIN d[234]
    DIRECTION INPUT ;
    USE SIGNAL ;
    PORT
      LAYER M4 ;
        RECT  -0.072 52.848 0.072 52.872 ;
    END
  END d[234]
  PIN d[235]
    DIRECTION INPUT ;
    USE SIGNAL ;
    PORT
      LAYER M4 ;
        RECT  -0.072 53.04 0.072 53.064 ;
    END
  END d[235]
  PIN d[236]
    DIRECTION INPUT ;
    USE SIGNAL ;
    PORT
      LAYER M4 ;
        RECT  -0.072 53.232 0.072 53.256 ;
    END
  END d[236]
  PIN d[237]
    DIRECTION INPUT ;
    USE SIGNAL ;
    PORT
      LAYER M4 ;
        RECT  -0.072 53.424 0.072 53.448 ;
    END
  END d[237]
  PIN d[238]
    DIRECTION INPUT ;
    USE SIGNAL ;
    PORT
      LAYER M4 ;
        RECT  -0.072 53.616 0.072 53.64 ;
    END
  END d[238]
  PIN d[239]
    DIRECTION INPUT ;
    USE SIGNAL ;
    PORT
      LAYER M4 ;
        RECT  -0.072 53.808 0.072 53.832 ;
    END
  END d[239]
  PIN d[23]
    DIRECTION INPUT ;
    USE SIGNAL ;
    PORT
      LAYER M4 ;
        RECT  -0.072 12.336 0.072 12.36 ;
    END
  END d[23]
  PIN d[240]
    DIRECTION INPUT ;
    USE SIGNAL ;
    PORT
      LAYER M4 ;
        RECT  -0.072 54 0.072 54.024 ;
    END
  END d[240]
  PIN d[241]
    DIRECTION INPUT ;
    USE SIGNAL ;
    PORT
      LAYER M4 ;
        RECT  -0.072 54.192 0.072 54.216 ;
    END
  END d[241]
  PIN d[242]
    DIRECTION INPUT ;
    USE SIGNAL ;
    PORT
      LAYER M4 ;
        RECT  -0.072 54.384 0.072 54.408 ;
    END
  END d[242]
  PIN d[243]
    DIRECTION INPUT ;
    USE SIGNAL ;
    PORT
      LAYER M4 ;
        RECT  -0.072 54.576 0.072 54.6 ;
    END
  END d[243]
  PIN d[244]
    DIRECTION INPUT ;
    USE SIGNAL ;
    PORT
      LAYER M4 ;
        RECT  -0.072 54.768 0.072 54.792 ;
    END
  END d[244]
  PIN d[245]
    DIRECTION INPUT ;
    USE SIGNAL ;
    PORT
      LAYER M4 ;
        RECT  -0.072 54.96 0.072 54.984 ;
    END
  END d[245]
  PIN d[246]
    DIRECTION INPUT ;
    USE SIGNAL ;
    PORT
      LAYER M4 ;
        RECT  -0.072 55.152 0.072 55.176 ;
    END
  END d[246]
  PIN d[247]
    DIRECTION INPUT ;
    USE SIGNAL ;
    PORT
      LAYER M4 ;
        RECT  -0.072 55.344 0.072 55.368 ;
    END
  END d[247]
  PIN d[248]
    DIRECTION INPUT ;
    USE SIGNAL ;
    PORT
      LAYER M4 ;
        RECT  -0.072 55.536 0.072 55.56 ;
    END
  END d[248]
  PIN d[249]
    DIRECTION INPUT ;
    USE SIGNAL ;
    PORT
      LAYER M4 ;
        RECT  -0.072 55.728 0.072 55.752 ;
    END
  END d[249]
  PIN d[24]
    DIRECTION INPUT ;
    USE SIGNAL ;
    PORT
      LAYER M4 ;
        RECT  -0.072 12.528 0.072 12.552 ;
    END
  END d[24]
  PIN d[250]
    DIRECTION INPUT ;
    USE SIGNAL ;
    PORT
      LAYER M4 ;
        RECT  -0.072 55.92 0.072 55.944 ;
    END
  END d[250]
  PIN d[251]
    DIRECTION INPUT ;
    USE SIGNAL ;
    PORT
      LAYER M4 ;
        RECT  -0.072 56.112 0.072 56.136 ;
    END
  END d[251]
  PIN d[252]
    DIRECTION INPUT ;
    USE SIGNAL ;
    PORT
      LAYER M4 ;
        RECT  -0.072 56.304 0.072 56.328 ;
    END
  END d[252]
  PIN d[253]
    DIRECTION INPUT ;
    USE SIGNAL ;
    PORT
      LAYER M4 ;
        RECT  -0.072 56.496 0.072 56.52 ;
    END
  END d[253]
  PIN d[254]
    DIRECTION INPUT ;
    USE SIGNAL ;
    PORT
      LAYER M4 ;
        RECT  -0.072 56.688 0.072 56.712 ;
    END
  END d[254]
  PIN d[255]
    DIRECTION INPUT ;
    USE SIGNAL ;
    PORT
      LAYER M4 ;
        RECT  -0.072 56.88 0.072 56.904 ;
    END
  END d[255]
  PIN d[25]
    DIRECTION INPUT ;
    USE SIGNAL ;
    PORT
      LAYER M4 ;
        RECT  -0.072 12.72 0.072 12.744 ;
    END
  END d[25]
  PIN d[26]
    DIRECTION INPUT ;
    USE SIGNAL ;
    PORT
      LAYER M4 ;
        RECT  -0.072 12.912 0.072 12.936 ;
    END
  END d[26]
  PIN d[27]
    DIRECTION INPUT ;
    USE SIGNAL ;
    PORT
      LAYER M4 ;
        RECT  -0.072 13.104 0.072 13.128 ;
    END
  END d[27]
  PIN d[28]
    DIRECTION INPUT ;
    USE SIGNAL ;
    PORT
      LAYER M4 ;
        RECT  -0.072 13.296 0.072 13.32 ;
    END
  END d[28]
  PIN d[29]
    DIRECTION INPUT ;
    USE SIGNAL ;
    PORT
      LAYER M4 ;
        RECT  -0.072 13.488 0.072 13.512 ;
    END
  END d[29]
  PIN d[2]
    DIRECTION INPUT ;
    USE SIGNAL ;
    PORT
      LAYER M4 ;
        RECT  -0.072 8.304 0.072 8.328 ;
    END
  END d[2]
  PIN d[30]
    DIRECTION INPUT ;
    USE SIGNAL ;
    PORT
      LAYER M4 ;
        RECT  -0.072 13.68 0.072 13.704 ;
    END
  END d[30]
  PIN d[31]
    DIRECTION INPUT ;
    USE SIGNAL ;
    PORT
      LAYER M4 ;
        RECT  -0.072 13.872 0.072 13.896 ;
    END
  END d[31]
  PIN d[32]
    DIRECTION INPUT ;
    USE SIGNAL ;
    PORT
      LAYER M4 ;
        RECT  -0.072 14.064 0.072 14.088 ;
    END
  END d[32]
  PIN d[33]
    DIRECTION INPUT ;
    USE SIGNAL ;
    PORT
      LAYER M4 ;
        RECT  -0.072 14.256 0.072 14.28 ;
    END
  END d[33]
  PIN d[34]
    DIRECTION INPUT ;
    USE SIGNAL ;
    PORT
      LAYER M4 ;
        RECT  -0.072 14.448 0.072 14.472 ;
    END
  END d[34]
  PIN d[35]
    DIRECTION INPUT ;
    USE SIGNAL ;
    PORT
      LAYER M4 ;
        RECT  -0.072 14.64 0.072 14.664 ;
    END
  END d[35]
  PIN d[36]
    DIRECTION INPUT ;
    USE SIGNAL ;
    PORT
      LAYER M4 ;
        RECT  -0.072 14.832 0.072 14.856 ;
    END
  END d[36]
  PIN d[37]
    DIRECTION INPUT ;
    USE SIGNAL ;
    PORT
      LAYER M4 ;
        RECT  -0.072 15.024 0.072 15.048 ;
    END
  END d[37]
  PIN d[38]
    DIRECTION INPUT ;
    USE SIGNAL ;
    PORT
      LAYER M4 ;
        RECT  -0.072 15.216 0.072 15.24 ;
    END
  END d[38]
  PIN d[39]
    DIRECTION INPUT ;
    USE SIGNAL ;
    PORT
      LAYER M4 ;
        RECT  -0.072 15.408 0.072 15.432 ;
    END
  END d[39]
  PIN d[3]
    DIRECTION INPUT ;
    USE SIGNAL ;
    PORT
      LAYER M4 ;
        RECT  -0.072 8.496 0.072 8.52 ;
    END
  END d[3]
  PIN d[40]
    DIRECTION INPUT ;
    USE SIGNAL ;
    PORT
      LAYER M4 ;
        RECT  -0.072 15.6 0.072 15.624 ;
    END
  END d[40]
  PIN d[41]
    DIRECTION INPUT ;
    USE SIGNAL ;
    PORT
      LAYER M4 ;
        RECT  -0.072 15.792 0.072 15.816 ;
    END
  END d[41]
  PIN d[42]
    DIRECTION INPUT ;
    USE SIGNAL ;
    PORT
      LAYER M4 ;
        RECT  -0.072 15.984 0.072 16.008 ;
    END
  END d[42]
  PIN d[43]
    DIRECTION INPUT ;
    USE SIGNAL ;
    PORT
      LAYER M4 ;
        RECT  -0.072 16.176 0.072 16.2 ;
    END
  END d[43]
  PIN d[44]
    DIRECTION INPUT ;
    USE SIGNAL ;
    PORT
      LAYER M4 ;
        RECT  -0.072 16.368 0.072 16.392 ;
    END
  END d[44]
  PIN d[45]
    DIRECTION INPUT ;
    USE SIGNAL ;
    PORT
      LAYER M4 ;
        RECT  -0.072 16.56 0.072 16.584 ;
    END
  END d[45]
  PIN d[46]
    DIRECTION INPUT ;
    USE SIGNAL ;
    PORT
      LAYER M4 ;
        RECT  -0.072 16.752 0.072 16.776 ;
    END
  END d[46]
  PIN d[47]
    DIRECTION INPUT ;
    USE SIGNAL ;
    PORT
      LAYER M4 ;
        RECT  -0.072 16.944 0.072 16.968 ;
    END
  END d[47]
  PIN d[48]
    DIRECTION INPUT ;
    USE SIGNAL ;
    PORT
      LAYER M4 ;
        RECT  -0.072 17.136 0.072 17.16 ;
    END
  END d[48]
  PIN d[49]
    DIRECTION INPUT ;
    USE SIGNAL ;
    PORT
      LAYER M4 ;
        RECT  -0.072 17.328 0.072 17.352 ;
    END
  END d[49]
  PIN d[4]
    DIRECTION INPUT ;
    USE SIGNAL ;
    PORT
      LAYER M4 ;
        RECT  -0.072 8.688 0.072 8.712 ;
    END
  END d[4]
  PIN d[50]
    DIRECTION INPUT ;
    USE SIGNAL ;
    PORT
      LAYER M4 ;
        RECT  -0.072 17.52 0.072 17.544 ;
    END
  END d[50]
  PIN d[51]
    DIRECTION INPUT ;
    USE SIGNAL ;
    PORT
      LAYER M4 ;
        RECT  -0.072 17.712 0.072 17.736 ;
    END
  END d[51]
  PIN d[52]
    DIRECTION INPUT ;
    USE SIGNAL ;
    PORT
      LAYER M4 ;
        RECT  -0.072 17.904 0.072 17.928 ;
    END
  END d[52]
  PIN d[53]
    DIRECTION INPUT ;
    USE SIGNAL ;
    PORT
      LAYER M4 ;
        RECT  -0.072 18.096 0.072 18.12 ;
    END
  END d[53]
  PIN d[54]
    DIRECTION INPUT ;
    USE SIGNAL ;
    PORT
      LAYER M4 ;
        RECT  -0.072 18.288 0.072 18.312 ;
    END
  END d[54]
  PIN d[55]
    DIRECTION INPUT ;
    USE SIGNAL ;
    PORT
      LAYER M4 ;
        RECT  -0.072 18.48 0.072 18.504 ;
    END
  END d[55]
  PIN d[56]
    DIRECTION INPUT ;
    USE SIGNAL ;
    PORT
      LAYER M4 ;
        RECT  -0.072 18.672 0.072 18.696 ;
    END
  END d[56]
  PIN d[57]
    DIRECTION INPUT ;
    USE SIGNAL ;
    PORT
      LAYER M4 ;
        RECT  -0.072 18.864 0.072 18.888 ;
    END
  END d[57]
  PIN d[58]
    DIRECTION INPUT ;
    USE SIGNAL ;
    PORT
      LAYER M4 ;
        RECT  -0.072 19.056 0.072 19.08 ;
    END
  END d[58]
  PIN d[59]
    DIRECTION INPUT ;
    USE SIGNAL ;
    PORT
      LAYER M4 ;
        RECT  -0.072 19.248 0.072 19.272 ;
    END
  END d[59]
  PIN d[5]
    DIRECTION INPUT ;
    USE SIGNAL ;
    PORT
      LAYER M4 ;
        RECT  -0.072 8.88 0.072 8.904 ;
    END
  END d[5]
  PIN d[60]
    DIRECTION INPUT ;
    USE SIGNAL ;
    PORT
      LAYER M4 ;
        RECT  -0.072 19.44 0.072 19.464 ;
    END
  END d[60]
  PIN d[61]
    DIRECTION INPUT ;
    USE SIGNAL ;
    PORT
      LAYER M4 ;
        RECT  -0.072 19.632 0.072 19.656 ;
    END
  END d[61]
  PIN d[62]
    DIRECTION INPUT ;
    USE SIGNAL ;
    PORT
      LAYER M4 ;
        RECT  -0.072 19.824 0.072 19.848 ;
    END
  END d[62]
  PIN d[63]
    DIRECTION INPUT ;
    USE SIGNAL ;
    PORT
      LAYER M4 ;
        RECT  -0.072 20.016 0.072 20.04 ;
    END
  END d[63]
  PIN d[64]
    DIRECTION INPUT ;
    USE SIGNAL ;
    PORT
      LAYER M4 ;
        RECT  -0.072 20.208 0.072 20.232 ;
    END
  END d[64]
  PIN d[65]
    DIRECTION INPUT ;
    USE SIGNAL ;
    PORT
      LAYER M4 ;
        RECT  -0.072 20.4 0.072 20.424 ;
    END
  END d[65]
  PIN d[66]
    DIRECTION INPUT ;
    USE SIGNAL ;
    PORT
      LAYER M4 ;
        RECT  -0.072 20.592 0.072 20.616 ;
    END
  END d[66]
  PIN d[67]
    DIRECTION INPUT ;
    USE SIGNAL ;
    PORT
      LAYER M4 ;
        RECT  -0.072 20.784 0.072 20.808 ;
    END
  END d[67]
  PIN d[68]
    DIRECTION INPUT ;
    USE SIGNAL ;
    PORT
      LAYER M4 ;
        RECT  -0.072 20.976 0.072 21 ;
    END
  END d[68]
  PIN d[69]
    DIRECTION INPUT ;
    USE SIGNAL ;
    PORT
      LAYER M4 ;
        RECT  -0.072 21.168 0.072 21.192 ;
    END
  END d[69]
  PIN d[6]
    DIRECTION INPUT ;
    USE SIGNAL ;
    PORT
      LAYER M4 ;
        RECT  -0.072 9.072 0.072 9.096 ;
    END
  END d[6]
  PIN d[70]
    DIRECTION INPUT ;
    USE SIGNAL ;
    PORT
      LAYER M4 ;
        RECT  -0.072 21.36 0.072 21.384 ;
    END
  END d[70]
  PIN d[71]
    DIRECTION INPUT ;
    USE SIGNAL ;
    PORT
      LAYER M4 ;
        RECT  -0.072 21.552 0.072 21.576 ;
    END
  END d[71]
  PIN d[72]
    DIRECTION INPUT ;
    USE SIGNAL ;
    PORT
      LAYER M4 ;
        RECT  -0.072 21.744 0.072 21.768 ;
    END
  END d[72]
  PIN d[73]
    DIRECTION INPUT ;
    USE SIGNAL ;
    PORT
      LAYER M4 ;
        RECT  -0.072 21.936 0.072 21.96 ;
    END
  END d[73]
  PIN d[74]
    DIRECTION INPUT ;
    USE SIGNAL ;
    PORT
      LAYER M4 ;
        RECT  -0.072 22.128 0.072 22.152 ;
    END
  END d[74]
  PIN d[75]
    DIRECTION INPUT ;
    USE SIGNAL ;
    PORT
      LAYER M4 ;
        RECT  -0.072 22.32 0.072 22.344 ;
    END
  END d[75]
  PIN d[76]
    DIRECTION INPUT ;
    USE SIGNAL ;
    PORT
      LAYER M4 ;
        RECT  -0.072 22.512 0.072 22.536 ;
    END
  END d[76]
  PIN d[77]
    DIRECTION INPUT ;
    USE SIGNAL ;
    PORT
      LAYER M4 ;
        RECT  -0.072 22.704 0.072 22.728 ;
    END
  END d[77]
  PIN d[78]
    DIRECTION INPUT ;
    USE SIGNAL ;
    PORT
      LAYER M4 ;
        RECT  -0.072 22.896 0.072 22.92 ;
    END
  END d[78]
  PIN d[79]
    DIRECTION INPUT ;
    USE SIGNAL ;
    PORT
      LAYER M4 ;
        RECT  -0.072 23.088 0.072 23.112 ;
    END
  END d[79]
  PIN d[7]
    DIRECTION INPUT ;
    USE SIGNAL ;
    PORT
      LAYER M4 ;
        RECT  -0.072 9.264 0.072 9.288 ;
    END
  END d[7]
  PIN d[80]
    DIRECTION INPUT ;
    USE SIGNAL ;
    PORT
      LAYER M4 ;
        RECT  -0.072 23.28 0.072 23.304 ;
    END
  END d[80]
  PIN d[81]
    DIRECTION INPUT ;
    USE SIGNAL ;
    PORT
      LAYER M4 ;
        RECT  -0.072 23.472 0.072 23.496 ;
    END
  END d[81]
  PIN d[82]
    DIRECTION INPUT ;
    USE SIGNAL ;
    PORT
      LAYER M4 ;
        RECT  -0.072 23.664 0.072 23.688 ;
    END
  END d[82]
  PIN d[83]
    DIRECTION INPUT ;
    USE SIGNAL ;
    PORT
      LAYER M4 ;
        RECT  -0.072 23.856 0.072 23.88 ;
    END
  END d[83]
  PIN d[84]
    DIRECTION INPUT ;
    USE SIGNAL ;
    PORT
      LAYER M4 ;
        RECT  -0.072 24.048 0.072 24.072 ;
    END
  END d[84]
  PIN d[85]
    DIRECTION INPUT ;
    USE SIGNAL ;
    PORT
      LAYER M4 ;
        RECT  -0.072 24.24 0.072 24.264 ;
    END
  END d[85]
  PIN d[86]
    DIRECTION INPUT ;
    USE SIGNAL ;
    PORT
      LAYER M4 ;
        RECT  -0.072 24.432 0.072 24.456 ;
    END
  END d[86]
  PIN d[87]
    DIRECTION INPUT ;
    USE SIGNAL ;
    PORT
      LAYER M4 ;
        RECT  -0.072 24.624 0.072 24.648 ;
    END
  END d[87]
  PIN d[88]
    DIRECTION INPUT ;
    USE SIGNAL ;
    PORT
      LAYER M4 ;
        RECT  -0.072 24.816 0.072 24.84 ;
    END
  END d[88]
  PIN d[89]
    DIRECTION INPUT ;
    USE SIGNAL ;
    PORT
      LAYER M4 ;
        RECT  -0.072 25.008 0.072 25.032 ;
    END
  END d[89]
  PIN d[8]
    DIRECTION INPUT ;
    USE SIGNAL ;
    PORT
      LAYER M4 ;
        RECT  -0.072 9.456 0.072 9.48 ;
    END
  END d[8]
  PIN d[90]
    DIRECTION INPUT ;
    USE SIGNAL ;
    PORT
      LAYER M4 ;
        RECT  -0.072 25.2 0.072 25.224 ;
    END
  END d[90]
  PIN d[91]
    DIRECTION INPUT ;
    USE SIGNAL ;
    PORT
      LAYER M4 ;
        RECT  -0.072 25.392 0.072 25.416 ;
    END
  END d[91]
  PIN d[92]
    DIRECTION INPUT ;
    USE SIGNAL ;
    PORT
      LAYER M4 ;
        RECT  -0.072 25.584 0.072 25.608 ;
    END
  END d[92]
  PIN d[93]
    DIRECTION INPUT ;
    USE SIGNAL ;
    PORT
      LAYER M4 ;
        RECT  -0.072 25.776 0.072 25.8 ;
    END
  END d[93]
  PIN d[94]
    DIRECTION INPUT ;
    USE SIGNAL ;
    PORT
      LAYER M4 ;
        RECT  -0.072 25.968 0.072 25.992 ;
    END
  END d[94]
  PIN d[95]
    DIRECTION INPUT ;
    USE SIGNAL ;
    PORT
      LAYER M4 ;
        RECT  -0.072 26.16 0.072 26.184 ;
    END
  END d[95]
  PIN d[96]
    DIRECTION INPUT ;
    USE SIGNAL ;
    PORT
      LAYER M4 ;
        RECT  -0.072 26.352 0.072 26.376 ;
    END
  END d[96]
  PIN d[97]
    DIRECTION INPUT ;
    USE SIGNAL ;
    PORT
      LAYER M4 ;
        RECT  -0.072 26.544 0.072 26.568 ;
    END
  END d[97]
  PIN d[98]
    DIRECTION INPUT ;
    USE SIGNAL ;
    PORT
      LAYER M4 ;
        RECT  -0.072 26.736 0.072 26.76 ;
    END
  END d[98]
  PIN d[99]
    DIRECTION INPUT ;
    USE SIGNAL ;
    PORT
      LAYER M4 ;
        RECT  -0.072 26.928 0.072 26.952 ;
    END
  END d[99]
  PIN d[9]
    DIRECTION INPUT ;
    USE SIGNAL ;
    PORT
      LAYER M4 ;
        RECT  -0.072 9.648 0.072 9.672 ;
    END
  END d[9]
  PIN q[0]
    DIRECTION OUTPUT ;
    USE SIGNAL ;
    PORT
      LAYER M4 ;
        RECT  64.728 26.352 64.872 26.376 ;
    END
  END q[0]
  PIN q[10]
    DIRECTION OUTPUT ;
    USE SIGNAL ;
    PORT
      LAYER M4 ;
        RECT  64.728 28.272 64.872 28.296 ;
    END
  END q[10]
  PIN q[11]
    DIRECTION OUTPUT ;
    USE SIGNAL ;
    PORT
      LAYER M4 ;
        RECT  64.728 28.464 64.872 28.488 ;
    END
  END q[11]
  PIN q[12]
    DIRECTION OUTPUT ;
    USE SIGNAL ;
    PORT
      LAYER M4 ;
        RECT  64.728 28.656 64.872 28.68 ;
    END
  END q[12]
  PIN q[13]
    DIRECTION OUTPUT ;
    USE SIGNAL ;
    PORT
      LAYER M4 ;
        RECT  64.728 28.848 64.872 28.872 ;
    END
  END q[13]
  PIN q[14]
    DIRECTION OUTPUT ;
    USE SIGNAL ;
    PORT
      LAYER M4 ;
        RECT  64.728 29.04 64.872 29.064 ;
    END
  END q[14]
  PIN q[15]
    DIRECTION OUTPUT ;
    USE SIGNAL ;
    PORT
      LAYER M4 ;
        RECT  64.728 29.232 64.872 29.256 ;
    END
  END q[15]
  PIN q[16]
    DIRECTION OUTPUT ;
    USE SIGNAL ;
    PORT
      LAYER M4 ;
        RECT  64.728 29.424 64.872 29.448 ;
    END
  END q[16]
  PIN q[17]
    DIRECTION OUTPUT ;
    USE SIGNAL ;
    PORT
      LAYER M4 ;
        RECT  64.728 29.616 64.872 29.64 ;
    END
  END q[17]
  PIN q[18]
    DIRECTION OUTPUT ;
    USE SIGNAL ;
    PORT
      LAYER M4 ;
        RECT  64.728 29.808 64.872 29.832 ;
    END
  END q[18]
  PIN q[19]
    DIRECTION OUTPUT ;
    USE SIGNAL ;
    PORT
      LAYER M4 ;
        RECT  64.728 30 64.872 30.024 ;
    END
  END q[19]
  PIN q[1]
    DIRECTION OUTPUT ;
    USE SIGNAL ;
    PORT
      LAYER M4 ;
        RECT  64.728 26.544 64.872 26.568 ;
    END
  END q[1]
  PIN q[20]
    DIRECTION OUTPUT ;
    USE SIGNAL ;
    PORT
      LAYER M4 ;
        RECT  64.728 30.192 64.872 30.216 ;
    END
  END q[20]
  PIN q[21]
    DIRECTION OUTPUT ;
    USE SIGNAL ;
    PORT
      LAYER M4 ;
        RECT  64.728 30.384 64.872 30.408 ;
    END
  END q[21]
  PIN q[22]
    DIRECTION OUTPUT ;
    USE SIGNAL ;
    PORT
      LAYER M4 ;
        RECT  64.728 30.576 64.872 30.6 ;
    END
  END q[22]
  PIN q[23]
    DIRECTION OUTPUT ;
    USE SIGNAL ;
    PORT
      LAYER M4 ;
        RECT  64.728 30.768 64.872 30.792 ;
    END
  END q[23]
  PIN q[24]
    DIRECTION OUTPUT ;
    USE SIGNAL ;
    PORT
      LAYER M4 ;
        RECT  64.728 30.96 64.872 30.984 ;
    END
  END q[24]
  PIN q[25]
    DIRECTION OUTPUT ;
    USE SIGNAL ;
    PORT
      LAYER M4 ;
        RECT  64.728 31.152 64.872 31.176 ;
    END
  END q[25]
  PIN q[26]
    DIRECTION OUTPUT ;
    USE SIGNAL ;
    PORT
      LAYER M4 ;
        RECT  64.728 31.344 64.872 31.368 ;
    END
  END q[26]
  PIN q[27]
    DIRECTION OUTPUT ;
    USE SIGNAL ;
    PORT
      LAYER M4 ;
        RECT  64.728 31.536 64.872 31.56 ;
    END
  END q[27]
  PIN q[28]
    DIRECTION OUTPUT ;
    USE SIGNAL ;
    PORT
      LAYER M4 ;
        RECT  64.728 31.728 64.872 31.752 ;
    END
  END q[28]
  PIN q[29]
    DIRECTION OUTPUT ;
    USE SIGNAL ;
    PORT
      LAYER M4 ;
        RECT  64.728 31.92 64.872 31.944 ;
    END
  END q[29]
  PIN q[2]
    DIRECTION OUTPUT ;
    USE SIGNAL ;
    PORT
      LAYER M4 ;
        RECT  64.728 26.736 64.872 26.76 ;
    END
  END q[2]
  PIN q[30]
    DIRECTION OUTPUT ;
    USE SIGNAL ;
    PORT
      LAYER M4 ;
        RECT  64.728 32.112 64.872 32.136 ;
    END
  END q[30]
  PIN q[31]
    DIRECTION OUTPUT ;
    USE SIGNAL ;
    PORT
      LAYER M4 ;
        RECT  64.728 32.304 64.872 32.328 ;
    END
  END q[31]
  PIN q[32]
    DIRECTION OUTPUT ;
    USE SIGNAL ;
    PORT
      LAYER M4 ;
        RECT  64.728 32.496 64.872 32.52 ;
    END
  END q[32]
  PIN q[33]
    DIRECTION OUTPUT ;
    USE SIGNAL ;
    PORT
      LAYER M4 ;
        RECT  64.728 32.688 64.872 32.712 ;
    END
  END q[33]
  PIN q[34]
    DIRECTION OUTPUT ;
    USE SIGNAL ;
    PORT
      LAYER M4 ;
        RECT  64.728 32.88 64.872 32.904 ;
    END
  END q[34]
  PIN q[35]
    DIRECTION OUTPUT ;
    USE SIGNAL ;
    PORT
      LAYER M4 ;
        RECT  64.728 33.072 64.872 33.096 ;
    END
  END q[35]
  PIN q[36]
    DIRECTION OUTPUT ;
    USE SIGNAL ;
    PORT
      LAYER M4 ;
        RECT  64.728 33.264 64.872 33.288 ;
    END
  END q[36]
  PIN q[37]
    DIRECTION OUTPUT ;
    USE SIGNAL ;
    PORT
      LAYER M4 ;
        RECT  64.728 33.456 64.872 33.48 ;
    END
  END q[37]
  PIN q[38]
    DIRECTION OUTPUT ;
    USE SIGNAL ;
    PORT
      LAYER M4 ;
        RECT  64.728 33.648 64.872 33.672 ;
    END
  END q[38]
  PIN q[39]
    DIRECTION OUTPUT ;
    USE SIGNAL ;
    PORT
      LAYER M4 ;
        RECT  64.728 33.84 64.872 33.864 ;
    END
  END q[39]
  PIN q[3]
    DIRECTION OUTPUT ;
    USE SIGNAL ;
    PORT
      LAYER M4 ;
        RECT  64.728 26.928 64.872 26.952 ;
    END
  END q[3]
  PIN q[40]
    DIRECTION OUTPUT ;
    USE SIGNAL ;
    PORT
      LAYER M4 ;
        RECT  64.728 34.032 64.872 34.056 ;
    END
  END q[40]
  PIN q[41]
    DIRECTION OUTPUT ;
    USE SIGNAL ;
    PORT
      LAYER M4 ;
        RECT  64.728 34.224 64.872 34.248 ;
    END
  END q[41]
  PIN q[42]
    DIRECTION OUTPUT ;
    USE SIGNAL ;
    PORT
      LAYER M4 ;
        RECT  64.728 34.416 64.872 34.44 ;
    END
  END q[42]
  PIN q[43]
    DIRECTION OUTPUT ;
    USE SIGNAL ;
    PORT
      LAYER M4 ;
        RECT  64.728 34.608 64.872 34.632 ;
    END
  END q[43]
  PIN q[44]
    DIRECTION OUTPUT ;
    USE SIGNAL ;
    PORT
      LAYER M4 ;
        RECT  64.728 34.8 64.872 34.824 ;
    END
  END q[44]
  PIN q[45]
    DIRECTION OUTPUT ;
    USE SIGNAL ;
    PORT
      LAYER M4 ;
        RECT  64.728 34.992 64.872 35.016 ;
    END
  END q[45]
  PIN q[46]
    DIRECTION OUTPUT ;
    USE SIGNAL ;
    PORT
      LAYER M4 ;
        RECT  64.728 35.184 64.872 35.208 ;
    END
  END q[46]
  PIN q[47]
    DIRECTION OUTPUT ;
    USE SIGNAL ;
    PORT
      LAYER M4 ;
        RECT  64.728 35.376 64.872 35.4 ;
    END
  END q[47]
  PIN q[48]
    DIRECTION OUTPUT ;
    USE SIGNAL ;
    PORT
      LAYER M4 ;
        RECT  64.728 35.568 64.872 35.592 ;
    END
  END q[48]
  PIN q[49]
    DIRECTION OUTPUT ;
    USE SIGNAL ;
    PORT
      LAYER M4 ;
        RECT  64.728 35.76 64.872 35.784 ;
    END
  END q[49]
  PIN q[4]
    DIRECTION OUTPUT ;
    USE SIGNAL ;
    PORT
      LAYER M4 ;
        RECT  64.728 27.12 64.872 27.144 ;
    END
  END q[4]
  PIN q[50]
    DIRECTION OUTPUT ;
    USE SIGNAL ;
    PORT
      LAYER M4 ;
        RECT  64.728 35.952 64.872 35.976 ;
    END
  END q[50]
  PIN q[51]
    DIRECTION OUTPUT ;
    USE SIGNAL ;
    PORT
      LAYER M4 ;
        RECT  64.728 36.144 64.872 36.168 ;
    END
  END q[51]
  PIN q[52]
    DIRECTION OUTPUT ;
    USE SIGNAL ;
    PORT
      LAYER M4 ;
        RECT  64.728 36.336 64.872 36.36 ;
    END
  END q[52]
  PIN q[53]
    DIRECTION OUTPUT ;
    USE SIGNAL ;
    PORT
      LAYER M4 ;
        RECT  64.728 36.528 64.872 36.552 ;
    END
  END q[53]
  PIN q[54]
    DIRECTION OUTPUT ;
    USE SIGNAL ;
    PORT
      LAYER M4 ;
        RECT  64.728 36.72 64.872 36.744 ;
    END
  END q[54]
  PIN q[55]
    DIRECTION OUTPUT ;
    USE SIGNAL ;
    PORT
      LAYER M4 ;
        RECT  64.728 36.912 64.872 36.936 ;
    END
  END q[55]
  PIN q[56]
    DIRECTION OUTPUT ;
    USE SIGNAL ;
    PORT
      LAYER M4 ;
        RECT  64.728 37.104 64.872 37.128 ;
    END
  END q[56]
  PIN q[57]
    DIRECTION OUTPUT ;
    USE SIGNAL ;
    PORT
      LAYER M4 ;
        RECT  64.728 37.296 64.872 37.32 ;
    END
  END q[57]
  PIN q[58]
    DIRECTION OUTPUT ;
    USE SIGNAL ;
    PORT
      LAYER M4 ;
        RECT  64.728 37.488 64.872 37.512 ;
    END
  END q[58]
  PIN q[59]
    DIRECTION OUTPUT ;
    USE SIGNAL ;
    PORT
      LAYER M4 ;
        RECT  64.728 37.68 64.872 37.704 ;
    END
  END q[59]
  PIN q[5]
    DIRECTION OUTPUT ;
    USE SIGNAL ;
    PORT
      LAYER M4 ;
        RECT  64.728 27.312 64.872 27.336 ;
    END
  END q[5]
  PIN q[60]
    DIRECTION OUTPUT ;
    USE SIGNAL ;
    PORT
      LAYER M4 ;
        RECT  64.728 37.872 64.872 37.896 ;
    END
  END q[60]
  PIN q[61]
    DIRECTION OUTPUT ;
    USE SIGNAL ;
    PORT
      LAYER M4 ;
        RECT  64.728 38.064 64.872 38.088 ;
    END
  END q[61]
  PIN q[62]
    DIRECTION OUTPUT ;
    USE SIGNAL ;
    PORT
      LAYER M4 ;
        RECT  64.728 38.256 64.872 38.28 ;
    END
  END q[62]
  PIN q[63]
    DIRECTION OUTPUT ;
    USE SIGNAL ;
    PORT
      LAYER M4 ;
        RECT  64.728 38.448 64.872 38.472 ;
    END
  END q[63]
  PIN q[6]
    DIRECTION OUTPUT ;
    USE SIGNAL ;
    PORT
      LAYER M4 ;
        RECT  64.728 27.504 64.872 27.528 ;
    END
  END q[6]
  PIN q[7]
    DIRECTION OUTPUT ;
    USE SIGNAL ;
    PORT
      LAYER M4 ;
        RECT  64.728 27.696 64.872 27.72 ;
    END
  END q[7]
  PIN q[8]
    DIRECTION OUTPUT ;
    USE SIGNAL ;
    PORT
      LAYER M4 ;
        RECT  64.728 27.888 64.872 27.912 ;
    END
  END q[8]
  PIN q[9]
    DIRECTION OUTPUT ;
    USE SIGNAL ;
    PORT
      LAYER M4 ;
        RECT  64.728 28.08 64.872 28.104 ;
    END
  END q[9]
  PIN stride1
    DIRECTION INPUT ;
    USE SIGNAL ;
    PORT
      LAYER M5 ;
        RECT  60.432 -0.072 60.456 0.072 ;
    END
  END stride1
  PIN v5
    DIRECTION INPUT ;
    USE SIGNAL ;
    PORT
      LAYER M5 ;
        RECT  58.32 -0.072 58.344 0.072 ;
    END
  END v5
  PIN v6
    DIRECTION INPUT ;
    USE SIGNAL ;
    PORT
      LAYER M5 ;
        RECT  58.896 -0.072 58.92 0.072 ;
    END
  END v6
  PIN v7
    DIRECTION INPUT ;
    USE SIGNAL ;
    PORT
      LAYER M5 ;
        RECT  59.472 -0.072 59.496 0.072 ;
    END
  END v7
  PIN VSS
    DIRECTION INOUT ;
    USE GROUND ;
    PORT
      LAYER M5 ;
        RECT  61.8 2.137 61.92 62.663 ;
        RECT  59.1 2.137 59.22 62.663 ;
        RECT  56.4 2.137 56.52 62.663 ;
        RECT  53.7 2.137 53.82 62.663 ;
        RECT  51 2.137 51.12 62.663 ;
        RECT  48.3 2.137 48.42 62.663 ;
        RECT  45.6 2.137 45.72 62.663 ;
        RECT  42.9 2.137 43.02 62.663 ;
        RECT  40.2 2.137 40.32 62.663 ;
        RECT  37.5 2.137 37.62 62.663 ;
        RECT  34.8 2.137 34.92 62.663 ;
        RECT  32.1 2.137 32.22 62.663 ;
        RECT  29.4 2.137 29.52 62.663 ;
        RECT  26.7 2.137 26.82 62.663 ;
        RECT  24 2.137 24.12 62.663 ;
        RECT  21.3 2.137 21.42 62.663 ;
        RECT  18.6 2.137 18.72 62.663 ;
        RECT  15.9 2.137 16.02 62.663 ;
        RECT  13.2 2.137 13.32 62.663 ;
        RECT  10.5 2.137 10.62 62.663 ;
        RECT  7.8 2.137 7.92 62.663 ;
        RECT  5.1 2.137 5.22 62.663 ;
        RECT  2.4 2.137 2.52 62.663 ;
    END
  END VSS
  PIN VDD
    DIRECTION INOUT ;
    USE POWER ;
    PORT
      LAYER M5 ;
        RECT  61.992 2.151 62.112 62.649 ;
        RECT  59.292 2.151 59.412 62.649 ;
        RECT  56.592 2.151 56.712 62.649 ;
        RECT  53.892 2.151 54.012 62.649 ;
        RECT  51.192 2.151 51.312 62.649 ;
        RECT  48.492 2.151 48.612 62.649 ;
        RECT  45.792 2.151 45.912 62.649 ;
        RECT  43.092 2.151 43.212 62.649 ;
        RECT  40.392 2.151 40.512 62.649 ;
        RECT  37.692 2.151 37.812 62.649 ;
        RECT  34.992 2.151 35.112 62.649 ;
        RECT  32.292 2.151 32.412 62.649 ;
        RECT  29.592 2.151 29.712 62.649 ;
        RECT  26.892 2.151 27.012 62.649 ;
        RECT  24.192 2.151 24.312 62.649 ;
        RECT  21.492 2.151 21.612 62.649 ;
        RECT  18.792 2.151 18.912 62.649 ;
        RECT  16.092 2.151 16.212 62.649 ;
        RECT  13.392 2.151 13.512 62.649 ;
        RECT  10.692 2.151 10.812 62.649 ;
        RECT  7.992 2.151 8.112 62.649 ;
        RECT  5.292 2.151 5.412 62.649 ;
        RECT  2.592 2.151 2.712 62.649 ;
    END
  END VDD
  OBS
    LAYER RVTN ;
     RECT  2.16 2.16 62.64 2.295 ;
     RECT  2.16 2.565 62.64 2.835 ;
     RECT  2.16 3.105 62.64 3.375 ;
     RECT  2.16 3.645 62.64 3.915 ;
     RECT  2.16 4.185 62.64 4.455 ;
     RECT  2.16 4.725 62.64 4.995 ;
     RECT  2.16 5.265 62.64 5.535 ;
     RECT  2.16 5.805 62.64 6.075 ;
     RECT  2.16 6.345 62.64 6.615 ;
     RECT  2.16 6.885 62.64 7.155 ;
     RECT  2.16 7.425 62.64 7.695 ;
     RECT  2.16 7.965 62.64 8.235 ;
     RECT  2.16 8.505 62.64 8.775 ;
     RECT  2.16 9.045 62.64 9.315 ;
     RECT  2.16 9.585 62.64 9.855 ;
     RECT  2.16 10.125 62.64 10.395 ;
     RECT  2.16 10.665 62.64 10.935 ;
     RECT  2.16 11.205 62.64 11.475 ;
     RECT  2.16 11.745 62.64 12.015 ;
     RECT  2.16 12.285 62.64 12.555 ;
     RECT  2.16 12.825 62.64 13.095 ;
     RECT  2.16 13.365 62.64 13.635 ;
     RECT  2.16 13.905 62.64 14.175 ;
     RECT  2.16 14.445 62.64 14.715 ;
     RECT  2.16 14.985 62.64 15.255 ;
     RECT  2.16 15.525 62.64 15.795 ;
     RECT  2.16 16.065 62.64 16.335 ;
     RECT  2.16 16.605 62.64 16.875 ;
     RECT  2.16 17.145 62.64 17.415 ;
     RECT  2.16 17.685 62.64 17.955 ;
     RECT  2.16 18.225 62.64 18.495 ;
     RECT  2.16 18.765 62.64 19.035 ;
     RECT  2.16 19.305 62.64 19.575 ;
     RECT  2.16 19.845 62.64 20.115 ;
     RECT  2.16 20.385 62.64 20.655 ;
     RECT  2.16 20.925 62.64 21.195 ;
     RECT  2.16 21.465 62.64 21.735 ;
     RECT  2.16 22.005 62.64 22.275 ;
     RECT  2.16 22.545 62.64 22.815 ;
     RECT  2.16 23.085 62.64 23.355 ;
     RECT  2.16 23.625 62.64 23.895 ;
     RECT  2.16 24.165 62.64 24.435 ;
     RECT  2.16 24.705 62.64 24.975 ;
     RECT  2.16 25.245 62.64 25.515 ;
     RECT  2.16 25.785 62.64 26.055 ;
     RECT  2.16 26.325 62.64 26.595 ;
     RECT  2.16 26.865 62.64 27.135 ;
     RECT  2.16 27.405 62.64 27.675 ;
     RECT  2.16 27.945 62.64 28.215 ;
     RECT  2.16 28.485 62.64 28.755 ;
     RECT  2.16 29.025 62.64 29.295 ;
     RECT  2.16 29.565 62.64 29.835 ;
     RECT  2.16 30.105 62.64 30.375 ;
     RECT  2.16 30.645 62.64 30.915 ;
     RECT  2.16 31.185 62.64 31.455 ;
     RECT  2.16 31.725 62.64 31.995 ;
     RECT  2.16 32.265 62.64 32.535 ;
     RECT  2.16 32.805 62.64 33.075 ;
     RECT  2.16 33.345 62.64 33.615 ;
     RECT  2.16 33.885 62.64 34.155 ;
     RECT  2.16 34.425 62.64 34.695 ;
     RECT  2.16 34.965 62.64 35.235 ;
     RECT  2.16 35.505 62.64 35.775 ;
     RECT  2.16 36.045 62.64 36.315 ;
     RECT  2.16 36.585 62.64 36.855 ;
     RECT  2.16 37.125 62.64 37.395 ;
     RECT  2.16 37.665 62.64 37.935 ;
     RECT  2.16 38.205 62.64 38.475 ;
     RECT  2.16 38.745 62.64 39.015 ;
     RECT  2.16 39.285 62.64 39.555 ;
     RECT  2.16 39.825 62.64 40.095 ;
     RECT  2.16 40.365 62.64 40.635 ;
     RECT  2.16 40.905 62.64 41.175 ;
     RECT  2.16 41.445 62.64 41.715 ;
     RECT  2.16 41.985 62.64 42.255 ;
     RECT  2.16 42.525 62.64 42.795 ;
     RECT  2.16 43.065 62.64 43.335 ;
     RECT  2.16 43.605 62.64 43.875 ;
     RECT  2.16 44.145 62.64 44.415 ;
     RECT  2.16 44.685 62.64 44.955 ;
     RECT  2.16 45.225 62.64 45.495 ;
     RECT  2.16 45.765 62.64 46.035 ;
     RECT  2.16 46.305 62.64 46.575 ;
     RECT  2.16 46.845 62.64 47.115 ;
     RECT  2.16 47.385 62.64 47.655 ;
     RECT  2.16 47.925 62.64 48.195 ;
     RECT  2.16 48.465 62.64 48.735 ;
     RECT  2.16 49.005 62.64 49.275 ;
     RECT  2.16 49.545 62.64 49.815 ;
     RECT  2.16 50.085 62.64 50.355 ;
     RECT  2.16 50.625 62.64 50.895 ;
     RECT  2.16 51.165 62.64 51.435 ;
     RECT  2.16 51.705 62.64 51.975 ;
     RECT  2.16 52.245 62.64 52.515 ;
     RECT  2.16 52.785 62.64 53.055 ;
     RECT  2.16 53.325 62.64 53.595 ;
     RECT  2.16 53.865 62.64 54.135 ;
     RECT  2.16 54.405 62.64 54.675 ;
     RECT  2.16 54.945 62.64 55.215 ;
     RECT  2.16 55.485 62.64 55.755 ;
     RECT  2.16 56.025 62.64 56.295 ;
     RECT  2.16 56.565 62.64 56.835 ;
     RECT  2.16 57.105 62.64 57.375 ;
     RECT  2.16 57.645 62.64 57.915 ;
     RECT  2.16 58.185 62.64 58.455 ;
     RECT  2.16 58.725 62.64 58.995 ;
     RECT  2.16 59.265 62.64 59.535 ;
     RECT  2.16 59.805 62.64 60.075 ;
     RECT  2.16 60.345 62.64 60.615 ;
     RECT  2.16 60.885 62.64 61.155 ;
     RECT  2.16 61.425 62.64 61.695 ;
     RECT  2.16 61.965 62.64 62.235 ;
     RECT  2.16 62.505 62.64 62.64 ;
    LAYER RVTP ;
     RECT  2.16 2.295 62.64 2.565 ;
     RECT  2.16 2.835 62.64 3.105 ;
     RECT  2.16 3.375 62.64 3.645 ;
     RECT  2.16 3.915 62.64 4.185 ;
     RECT  2.16 4.455 62.64 4.725 ;
     RECT  2.16 4.995 62.64 5.265 ;
     RECT  2.16 5.535 62.64 5.805 ;
     RECT  2.16 6.075 62.64 6.345 ;
     RECT  2.16 6.615 62.64 6.885 ;
     RECT  2.16 7.155 62.64 7.425 ;
     RECT  2.16 7.695 62.64 7.965 ;
     RECT  2.16 8.235 62.64 8.505 ;
     RECT  2.16 8.775 62.64 9.045 ;
     RECT  2.16 9.315 62.64 9.585 ;
     RECT  2.16 9.855 62.64 10.125 ;
     RECT  2.16 10.395 62.64 10.665 ;
     RECT  2.16 10.935 62.64 11.205 ;
     RECT  2.16 11.475 62.64 11.745 ;
     RECT  2.16 12.015 62.64 12.285 ;
     RECT  2.16 12.555 62.64 12.825 ;
     RECT  2.16 13.095 62.64 13.365 ;
     RECT  2.16 13.635 62.64 13.905 ;
     RECT  2.16 14.175 62.64 14.445 ;
     RECT  2.16 14.715 62.64 14.985 ;
     RECT  2.16 15.255 62.64 15.525 ;
     RECT  2.16 15.795 62.64 16.065 ;
     RECT  2.16 16.335 62.64 16.605 ;
     RECT  2.16 16.875 62.64 17.145 ;
     RECT  2.16 17.415 62.64 17.685 ;
     RECT  2.16 17.955 62.64 18.225 ;
     RECT  2.16 18.495 62.64 18.765 ;
     RECT  2.16 19.035 62.64 19.305 ;
     RECT  2.16 19.575 62.64 19.845 ;
     RECT  2.16 20.115 62.64 20.385 ;
     RECT  2.16 20.655 62.64 20.925 ;
     RECT  2.16 21.195 62.64 21.465 ;
     RECT  2.16 21.735 62.64 22.005 ;
     RECT  2.16 22.275 62.64 22.545 ;
     RECT  2.16 22.815 62.64 23.085 ;
     RECT  2.16 23.355 62.64 23.625 ;
     RECT  2.16 23.895 62.64 24.165 ;
     RECT  2.16 24.435 62.64 24.705 ;
     RECT  2.16 24.975 62.64 25.245 ;
     RECT  2.16 25.515 62.64 25.785 ;
     RECT  2.16 26.055 62.64 26.325 ;
     RECT  2.16 26.595 62.64 26.865 ;
     RECT  2.16 27.135 62.64 27.405 ;
     RECT  2.16 27.675 62.64 27.945 ;
     RECT  2.16 28.215 62.64 28.485 ;
     RECT  2.16 28.755 62.64 29.025 ;
     RECT  2.16 29.295 62.64 29.565 ;
     RECT  2.16 29.835 62.64 30.105 ;
     RECT  2.16 30.375 62.64 30.645 ;
     RECT  2.16 30.915 62.64 31.185 ;
     RECT  2.16 31.455 62.64 31.725 ;
     RECT  2.16 31.995 62.64 32.265 ;
     RECT  2.16 32.535 62.64 32.805 ;
     RECT  2.16 33.075 62.64 33.345 ;
     RECT  2.16 33.615 62.64 33.885 ;
     RECT  2.16 34.155 62.64 34.425 ;
     RECT  2.16 34.695 62.64 34.965 ;
     RECT  2.16 35.235 62.64 35.505 ;
     RECT  2.16 35.775 62.64 36.045 ;
     RECT  2.16 36.315 62.64 36.585 ;
     RECT  2.16 36.855 62.64 37.125 ;
     RECT  2.16 37.395 62.64 37.665 ;
     RECT  2.16 37.935 62.64 38.205 ;
     RECT  2.16 38.475 62.64 38.745 ;
     RECT  2.16 39.015 62.64 39.285 ;
     RECT  2.16 39.555 62.64 39.825 ;
     RECT  2.16 40.095 62.64 40.365 ;
     RECT  2.16 40.635 62.64 40.905 ;
     RECT  2.16 41.175 62.64 41.445 ;
     RECT  2.16 41.715 62.64 41.985 ;
     RECT  2.16 42.255 62.64 42.525 ;
     RECT  2.16 42.795 62.64 43.065 ;
     RECT  2.16 43.335 62.64 43.605 ;
     RECT  2.16 43.875 62.64 44.145 ;
     RECT  2.16 44.415 62.64 44.685 ;
     RECT  2.16 44.955 62.64 45.225 ;
     RECT  2.16 45.495 62.64 45.765 ;
     RECT  2.16 46.035 62.64 46.305 ;
     RECT  2.16 46.575 62.64 46.845 ;
     RECT  2.16 47.115 62.64 47.385 ;
     RECT  2.16 47.655 62.64 47.925 ;
     RECT  2.16 48.195 62.64 48.465 ;
     RECT  2.16 48.735 62.64 49.005 ;
     RECT  2.16 49.275 62.64 49.545 ;
     RECT  2.16 49.815 62.64 50.085 ;
     RECT  2.16 50.355 62.64 50.625 ;
     RECT  2.16 50.895 62.64 51.165 ;
     RECT  2.16 51.435 62.64 51.705 ;
     RECT  2.16 51.975 62.64 52.245 ;
     RECT  2.16 52.515 62.64 52.785 ;
     RECT  2.16 53.055 62.64 53.325 ;
     RECT  2.16 53.595 62.64 53.865 ;
     RECT  2.16 54.135 62.64 54.405 ;
     RECT  2.16 54.675 62.64 54.945 ;
     RECT  2.16 55.215 62.64 55.485 ;
     RECT  2.16 55.755 62.64 56.025 ;
     RECT  2.16 56.295 62.64 56.565 ;
     RECT  2.16 56.835 62.64 57.105 ;
     RECT  2.16 57.375 62.64 57.645 ;
     RECT  2.16 57.915 62.64 58.185 ;
     RECT  2.16 58.455 62.64 58.725 ;
     RECT  2.16 58.995 62.64 59.265 ;
     RECT  2.16 59.535 62.64 59.805 ;
     RECT  2.16 60.075 62.64 60.345 ;
     RECT  2.16 60.615 62.64 60.885 ;
     RECT  2.16 61.155 62.64 61.425 ;
     RECT  2.16 61.695 62.64 61.965 ;
     RECT  2.16 62.235 62.64 62.505 ;
    LAYER M1 ;
     RECT  2.16 2.151 62.64 62.649 ;
    LAYER M2 ;
     RECT  0.067 17.082 2.16 17.1 ;
     RECT  0.535 30.15 2.16 30.168 ;
     RECT  0.067 33.012 2.16 33.03 ;
     RECT  0.067 34.74 2.16 34.758 ;
     RECT  0.535 43.848 2.16 44.442 ;
     RECT  0.067 50.67 2.16 50.688 ;
     RECT  0.067 52.992 2.16 53.01 ;
     RECT  2.16 2.151 62.64 62.649 ;
     RECT  62.64 25.686 62.735 39.474 ;
     RECT  62.735 29.916 63.239 39.474 ;
     RECT  62.735 25.686 63.275 28.242 ;
     RECT  63.239 29.916 63.275 37.584 ;
     RECT  63.275 25.686 63.311 27.9 ;
     RECT  63.275 29.916 63.311 33.714 ;
     RECT  63.275 34.596 63.311 37.584 ;
     RECT  63.311 25.686 63.383 26.514 ;
     RECT  63.239 38.484 63.815 39.384 ;
     RECT  63.383 25.686 63.851 26.388 ;
     RECT  63.311 30.348 63.851 33.714 ;
     RECT  63.311 34.596 63.851 34.884 ;
     RECT  63.311 35.946 63.851 36.576 ;
     RECT  63.311 37.566 63.851 37.584 ;
     RECT  63.815 38.484 63.851 38.502 ;
     RECT  63.851 25.686 63.887 25.704 ;
     RECT  63.311 27.576 63.887 27.9 ;
     RECT  63.851 30.348 63.887 31.644 ;
     RECT  63.851 33.012 63.887 33.714 ;
     RECT  63.887 27.576 63.923 27.594 ;
     RECT  63.851 34.596 63.923 34.614 ;
     RECT  62.735 29.106 64.715 29.124 ;
     RECT  63.887 30.348 64.715 30.366 ;
     RECT  63.851 36.558 64.715 36.576 ;
     RECT  63.815 39.366 64.715 39.384 ;
    LAYER M3 ;
     RECT  42.228 0.571 42.246 1.723 ;
     RECT  45.756 0.571 45.774 1.723 ;
     RECT  51.948 0.571 51.966 1.723 ;
     RECT  54.756 0.571 54.774 1.723 ;
     RECT  57.744 0.571 57.762 1.723 ;
     RECT  58.86 0.571 58.878 1.723 ;
     RECT  23.472 1.723 23.994 2.143 ;
     RECT  41.76 1.723 42.822 2.143 ;
     RECT  49.284 1.723 50.418 2.143 ;
     RECT  51.192 1.723 51.21 2.143 ;
     RECT  54.756 1.723 55.89 2.143 ;
     RECT  56.628 1.723 56.646 2.143 ;
     RECT  43.884 1.723 45.774 2.255 ;
     RECT  49.284 2.143 51.21 2.255 ;
     RECT  51.948 1.723 53.874 2.255 ;
     RECT  54.756 2.143 56.646 2.255 ;
     RECT  60.444 0.571 60.462 2.255 ;
     RECT  9.216 0.571 9.234 2.291 ;
     RECT  46.764 0.571 48.474 2.291 ;
     RECT  57.744 1.723 59.382 2.291 ;
     RECT  23.472 2.143 24.105 2.371 ;
     RECT  25.092 0.571 25.11 2.371 ;
     RECT  41.76 2.143 43.005 2.371 ;
     RECT  49.752 2.255 51.21 2.371 ;
     RECT  52.416 2.255 53.874 2.371 ;
     RECT  54.756 2.255 54.846 2.371 ;
     RECT  55.584 2.255 56.646 2.371 ;
     RECT  2.415 2.143 2.505 2.413 ;
     RECT  5.115 2.143 5.205 2.413 ;
     RECT  7.815 2.143 7.905 2.413 ;
     RECT  8.676 2.371 8.946 2.413 ;
     RECT  10.515 2.143 10.605 2.413 ;
     RECT  13.215 2.143 13.305 2.413 ;
     RECT  15.915 2.143 16.005 2.413 ;
     RECT  18.615 2.143 18.705 2.413 ;
     RECT  21.315 2.143 21.405 2.413 ;
     RECT  23.472 2.371 24.174 2.413 ;
     RECT  26.715 2.143 26.805 2.413 ;
     RECT  29.415 2.143 29.505 2.413 ;
     RECT  32.115 2.143 32.205 2.413 ;
     RECT  34.815 2.143 34.905 2.413 ;
     RECT  37.515 2.143 37.605 2.413 ;
     RECT  40.215 2.143 40.305 2.413 ;
     RECT  41.508 2.371 43.005 2.413 ;
     RECT  43.812 2.263 43.83 2.413 ;
     RECT  44.64 2.255 45.774 2.413 ;
     RECT  47.052 2.291 48.474 2.413 ;
     RECT  58.176 2.291 59.382 2.413 ;
     RECT  61.815 2.143 61.905 2.413 ;
     RECT  7.815 2.413 8.946 2.489 ;
     RECT  25.02 2.371 25.11 2.489 ;
     RECT  23.472 2.413 24.297 2.641 ;
     RECT  44.64 2.413 45.897 2.641 ;
     RECT  58.176 2.413 59.397 3.137 ;
     RECT  40.215 2.413 40.497 3.145 ;
     RECT  41.508 2.413 43.83 3.145 ;
     RECT  52.416 2.371 54.846 3.145 ;
     RECT  55.584 2.371 57.33 3.145 ;
     RECT  44.64 2.641 45.99 3.197 ;
     RECT  52.416 3.145 57.726 3.197 ;
     RECT  40.215 3.145 43.83 3.299 ;
     RECT  52.416 3.197 57.33 3.299 ;
     RECT  34.815 2.413 35.097 3.307 ;
     RECT  44.676 3.197 45.99 3.344 ;
     RECT  52.416 3.299 54.45 3.389 ;
     RECT  47.052 2.413 48.906 3.403 ;
     RECT  46.908 3.403 48.906 3.437 ;
     RECT  8.928 2.489 8.946 3.451 ;
     RECT  23.472 2.641 24.39 3.451 ;
     RECT  13.215 2.413 13.497 3.547 ;
     RECT  8.928 3.451 9.162 3.569 ;
     RECT  23.256 3.451 24.39 3.643 ;
     RECT  13.215 3.547 13.59 3.677 ;
     RECT  14.832 3.547 14.85 3.677 ;
     RECT  7.815 2.489 8.097 3.721 ;
     RECT  22.536 3.643 24.39 3.721 ;
     RECT  25.164 2.641 25.182 3.721 ;
     RECT  45 3.344 45.99 3.721 ;
     RECT  46.908 3.437 47.07 3.721 ;
     RECT  47.88 3.437 48.906 3.721 ;
     RECT  53.496 3.389 54.45 3.725 ;
     RECT  7.815 3.721 8.766 3.773 ;
     RECT  45 3.721 47.07 3.839 ;
     RECT  38.772 3.181 38.79 3.847 ;
     RECT  22.536 3.721 25.182 3.875 ;
     RECT  38.52 3.847 38.79 3.875 ;
     RECT  45 3.839 46.926 3.875 ;
     RECT  55.512 3.299 57.33 3.965 ;
     RECT  55.548 3.965 57.33 3.983 ;
     RECT  24.015 3.875 25.182 3.991 ;
     RECT  49.752 2.371 51.462 3.991 ;
     RECT  24.015 3.991 25.362 4.109 ;
     RECT  41.976 3.299 43.83 4.109 ;
     RECT  45 3.875 46.458 4.123 ;
     RECT  53.715 3.725 54.45 4.123 ;
     RECT  22.536 3.875 22.842 4.157 ;
     RECT  41.976 4.109 43.47 4.157 ;
     RECT  40.215 3.299 40.497 4.189 ;
     RECT  44.712 4.123 46.458 4.217 ;
     RECT  47.88 3.721 48.942 4.219 ;
     RECT  49.752 3.991 51.534 4.219 ;
     RECT  52.416 3.389 52.722 4.219 ;
     RECT  58.644 3.137 59.397 4.219 ;
     RECT  52.308 4.219 52.722 4.259 ;
     RECT  58.572 4.219 59.397 4.259 ;
     RECT  32.115 2.413 32.397 4.261 ;
     RECT  56.376 3.983 57.33 4.261 ;
     RECT  58.644 4.259 59.397 4.261 ;
     RECT  60.12 2.263 60.138 4.261 ;
     RECT  41.976 4.157 41.994 4.289 ;
     RECT  42.768 4.157 43.197 4.289 ;
     RECT  18.615 2.413 18.897 4.351 ;
     RECT  53.715 4.123 54.522 4.379 ;
     RECT  58.644 4.261 60.138 4.379 ;
     RECT  24.015 4.109 25.218 4.451 ;
     RECT  25.2 4.451 25.218 4.541 ;
     RECT  22.824 4.157 22.842 4.559 ;
     RECT  2.415 2.413 2.697 7.735 ;
     RECT  2.415 7.735 3.15 7.771 ;
     RECT  2.415 7.771 3.438 7.949 ;
     RECT  2.415 7.949 2.697 8.107 ;
     RECT  7.815 3.773 8.097 8.107 ;
     RECT  3.42 7.949 3.438 8.275 ;
     RECT  4.212 7.861 4.23 8.275 ;
     RECT  5.115 2.413 5.397 8.401 ;
     RECT  7.815 8.107 8.55 8.429 ;
     RECT  3.42 8.275 4.23 8.509 ;
     RECT  3.42 8.509 4.302 8.545 ;
     RECT  5.115 8.401 5.778 8.545 ;
     RECT  3.42 8.545 5.778 8.851 ;
     RECT  2.304 8.107 2.697 9.013 ;
     RECT  3.42 8.851 5.958 9.013 ;
     RECT  2.304 9.013 5.958 9.067 ;
     RECT  2.304 9.067 6.138 9.481 ;
     RECT  2.304 9.481 6.858 9.499 ;
     RECT  7.815 8.429 8.478 9.499 ;
     RECT  2.304 9.499 8.478 9.545 ;
     RECT  2.304 9.545 6.858 9.653 ;
     RECT  0.072 9.547 0.09 9.677 ;
     RECT  9.684 3.721 9.702 10.201 ;
     RECT  2.304 9.653 6.534 10.205 ;
     RECT  0.072 10.699 0.09 10.829 ;
     RECT  7.815 9.545 8.478 10.843 ;
     RECT  7.632 10.843 8.478 11.011 ;
     RECT  2.304 10.205 6.39 11.209 ;
     RECT  7.164 11.011 8.478 11.209 ;
     RECT  2.304 11.209 8.478 11.281 ;
     RECT  9.216 10.201 9.702 11.281 ;
     RECT  24.015 4.451 24.297 14.521 ;
     RECT  56.376 4.261 57.798 14.549 ;
     RECT  10.515 2.413 10.797 15.961 ;
     RECT  10.515 15.961 11.826 15.979 ;
     RECT  2.304 11.281 9.702 16.171 ;
     RECT  60.336 4.531 60.354 16.259 ;
     RECT  10.515 15.979 12.33 16.339 ;
     RECT  15.915 2.413 16.197 16.339 ;
     RECT  2.268 16.171 9.702 16.367 ;
     RECT  14.652 15.961 14.886 16.375 ;
     RECT  2.304 16.367 9.702 16.411 ;
     RECT  10.476 16.339 12.33 16.411 ;
     RECT  13.215 3.677 13.497 16.411 ;
     RECT  2.304 16.411 12.33 16.501 ;
     RECT  13.14 16.411 13.497 16.501 ;
     RECT  15.84 16.339 16.197 16.501 ;
     RECT  45.252 4.217 46.458 16.537 ;
     RECT  45.252 16.537 46.782 16.609 ;
     RECT  47.88 4.219 51.534 16.609 ;
     RECT  2.304 16.501 13.497 16.645 ;
     RECT  14.508 16.375 14.886 16.645 ;
     RECT  58.644 4.379 59.526 16.709 ;
     RECT  2.304 16.645 14.886 16.807 ;
     RECT  15.66 16.501 16.197 16.807 ;
     RECT  16.992 16.795 17.01 16.807 ;
     RECT  45.252 16.609 51.534 16.807 ;
     RECT  2.304 16.807 17.01 16.835 ;
     RECT  44.64 16.807 51.534 16.879 ;
     RECT  42.915 4.289 43.197 16.951 ;
     RECT  44.496 16.879 51.534 16.951 ;
     RECT  42.915 16.951 43.578 17.077 ;
     RECT  44.316 16.951 51.534 17.077 ;
     RECT  52.704 4.259 52.722 17.113 ;
     RECT  53.715 4.379 54.45 17.141 ;
     RECT  42.444 17.077 51.534 17.149 ;
     RECT  0.072 17.077 0.09 17.165 ;
     RECT  42.408 17.149 51.534 17.185 ;
     RECT  18 4.351 18.897 17.221 ;
     RECT  40.215 4.189 40.77 17.221 ;
     RECT  42.228 17.185 51.534 17.311 ;
     RECT  40.215 17.221 41.094 17.347 ;
     RECT  52.416 17.113 52.722 17.347 ;
     RECT  40.176 17.347 41.094 17.419 ;
     RECT  42.048 17.311 51.534 17.419 ;
     RECT  55.548 3.983 55.638 17.419 ;
     RECT  52.416 17.347 52.794 17.447 ;
     RECT  40.176 17.419 51.534 17.491 ;
     RECT  2.304 16.835 16.362 17.581 ;
     RECT  40.032 17.491 51.534 17.581 ;
     RECT  52.416 17.447 52.722 17.581 ;
     RECT  2.304 17.581 16.83 17.659 ;
     RECT  17.568 17.221 18.897 17.659 ;
     RECT  40.032 17.581 52.722 17.959 ;
     RECT  38.52 3.875 38.538 17.995 ;
     RECT  2.304 17.659 18.897 18.283 ;
     RECT  37.515 2.413 37.797 18.427 ;
     RECT  38.52 17.995 38.79 18.427 ;
     RECT  37.515 18.427 38.79 18.535 ;
     RECT  39.708 17.959 52.722 18.535 ;
     RECT  37.515 18.535 52.722 18.931 ;
     RECT  2.268 18.283 18.897 19.067 ;
     RECT  34.815 3.307 35.586 19.075 ;
     RECT  37.515 18.931 52.83 19.201 ;
     RECT  53.715 17.141 54.09 19.201 ;
     RECT  37.515 19.201 54.09 19.237 ;
     RECT  37.332 19.237 54.09 19.345 ;
     RECT  37.116 19.345 54.09 19.381 ;
     RECT  55.188 17.419 55.638 19.651 ;
     RECT  55.116 19.651 55.638 19.679 ;
     RECT  36.972 19.381 54.09 19.777 ;
     RECT  36.756 19.777 54.09 19.885 ;
     RECT  36.648 19.885 54.09 20.011 ;
     RECT  34.488 19.075 35.586 20.059 ;
     RECT  36.36 20.011 54.09 20.059 ;
     RECT  2.304 19.067 18.897 20.453 ;
     RECT  34.488 20.059 54.09 20.461 ;
     RECT  55.116 19.679 55.566 20.461 ;
     RECT  34.488 20.461 55.566 20.551 ;
     RECT  56.376 14.549 56.697 20.551 ;
     RECT  57.78 14.549 57.798 20.551 ;
     RECT  25.416 20.587 25.434 20.731 ;
     RECT  34.38 20.551 55.566 20.731 ;
     RECT  25.416 20.731 25.65 20.779 ;
     RECT  31.788 4.261 32.397 20.821 ;
     RECT  33.516 20.299 33.534 20.821 ;
     RECT  25.38 20.779 25.65 20.849 ;
     RECT  31.788 20.821 33.534 20.893 ;
     RECT  22.788 20.827 22.806 20.957 ;
     RECT  31.572 20.893 33.534 20.993 ;
     RECT  56.376 20.551 57.798 20.993 ;
     RECT  20.052 21.001 20.07 21.053 ;
     RECT  31.572 20.993 32.397 21.091 ;
     RECT  34.344 20.731 55.566 21.091 ;
     RECT  2.304 20.453 10.854 21.155 ;
     RECT  33.516 20.993 33.534 21.163 ;
     RECT  34.308 21.091 55.566 21.163 ;
     RECT  33.516 21.163 55.566 21.355 ;
     RECT  56.376 20.993 57.366 21.355 ;
     RECT  0.072 21.451 0.09 21.581 ;
     RECT  29.415 2.413 29.697 21.631 ;
     RECT  30.528 21.115 30.546 21.631 ;
     RECT  23.688 14.521 24.297 21.643 ;
     RECT  26.715 2.413 26.997 21.643 ;
     RECT  29.415 21.631 30.546 21.667 ;
     RECT  31.428 21.091 32.397 21.667 ;
     RECT  21.315 2.413 21.597 21.739 ;
     RECT  29.415 21.667 32.397 21.739 ;
     RECT  20.592 21.739 21.597 21.811 ;
     RECT  29.088 21.739 32.397 21.811 ;
     RECT  33.516 21.355 57.366 21.811 ;
     RECT  33.48 21.811 57.366 21.937 ;
     RECT  28.584 21.811 32.397 21.973 ;
     RECT  33.408 21.937 57.366 21.973 ;
     RECT  2.376 21.155 10.854 22.009 ;
     RECT  11.592 20.453 18.897 22.009 ;
     RECT  28.584 21.973 57.366 22.009 ;
     RECT  28.476 22.009 57.366 22.037 ;
     RECT  20.52 21.811 21.597 22.081 ;
     RECT  23.688 21.643 24.678 22.081 ;
     RECT  26.1 21.643 26.997 22.081 ;
     RECT  2.376 22.009 18.897 22.123 ;
     RECT  20.52 22.081 22.122 22.207 ;
     RECT  22.86 21.739 22.878 22.207 ;
     RECT  20.52 22.207 22.878 22.243 ;
     RECT  2.304 22.123 18.897 22.279 ;
     RECT  20.52 22.243 22.95 22.351 ;
     RECT  23.688 22.081 26.997 22.351 ;
     RECT  2.304 22.279 18.954 22.549 ;
     RECT  2.304 22.549 19.026 22.589 ;
     RECT  2.304 22.589 18.918 22.613 ;
     RECT  20.16 22.351 27.09 22.621 ;
     RECT  20.16 22.621 27.414 22.711 ;
     RECT  59.115 16.709 59.526 22.747 ;
     RECT  28.476 22.037 28.602 22.855 ;
     RECT  29.415 22.037 57.366 22.855 ;
     RECT  20.016 22.711 27.738 22.981 ;
     RECT  28.476 22.855 57.366 22.981 ;
     RECT  20.016 22.981 57.366 23.089 ;
     RECT  58.284 21.973 58.302 23.089 ;
     RECT  20.016 23.089 58.302 23.251 ;
     RECT  2.304 22.613 18.897 23.315 ;
     RECT  19.944 23.251 58.302 23.315 ;
     RECT  2.34 23.315 18.897 23.431 ;
     RECT  59.115 22.747 60.21 23.621 ;
     RECT  2.34 23.431 18.954 23.701 ;
     RECT  19.944 23.315 20.106 23.701 ;
     RECT  20.988 23.315 58.302 23.899 ;
     RECT  2.34 23.701 20.106 23.981 ;
     RECT  2.34 23.981 15.066 24.043 ;
     RECT  15.84 23.981 20.106 24.061 ;
     RECT  20.988 23.899 58.374 24.061 ;
     RECT  15.84 24.061 58.374 24.089 ;
     RECT  2.304 24.043 15.066 24.781 ;
     RECT  15.84 24.089 58.302 24.781 ;
     RECT  2.304 24.781 58.302 25.519 ;
     RECT  59.115 23.621 59.397 25.519 ;
     RECT  61.815 2.413 62.097 25.555 ;
     RECT  61.815 25.555 62.334 25.591 ;
     RECT  61.815 25.591 62.514 25.789 ;
     RECT  61.416 25.789 62.514 25.825 ;
     RECT  63.864 25.681 63.882 25.951 ;
     RECT  2.304 25.519 59.397 26.095 ;
     RECT  60.192 23.621 60.21 26.095 ;
     RECT  2.304 26.095 60.354 26.131 ;
     RECT  61.164 25.825 62.514 26.131 ;
     RECT  63.288 25.951 63.882 26.765 ;
     RECT  2.304 26.131 62.514 26.923 ;
     RECT  2.268 26.923 62.514 27.533 ;
     RECT  63.288 26.765 63.378 27.571 ;
     RECT  2.268 27.533 62.334 27.707 ;
     RECT  63.288 27.571 63.918 27.883 ;
     RECT  2.304 27.707 62.334 28.381 ;
     RECT  63.252 27.883 63.918 28.493 ;
     RECT  63.252 28.493 63.306 28.685 ;
     RECT  2.304 28.381 62.37 28.723 ;
     RECT  64.692 29.035 64.71 29.129 ;
     RECT  2.304 28.723 62.73 29.645 ;
     RECT  2.304 29.645 62.442 29.837 ;
     RECT  2.304 29.837 62.298 30.029 ;
     RECT  2.304 30.029 62.262 30.101 ;
     RECT  2.304 30.101 19.818 30.187 ;
     RECT  63.288 29.911 63.306 30.379 ;
     RECT  0.54 30.145 0.558 30.413 ;
     RECT  20.592 30.101 62.262 30.569 ;
     RECT  2.268 30.187 19.818 30.605 ;
     RECT  21.24 30.569 62.262 30.641 ;
     RECT  0.072 30.763 0.09 30.893 ;
     RECT  64.692 29.995 64.71 30.893 ;
     RECT  21.276 30.641 62.262 30.955 ;
     RECT  21.276 30.955 62.298 31.019 ;
     RECT  63.288 30.379 63.846 31.081 ;
     RECT  2.304 30.605 19.818 31.261 ;
     RECT  2.304 31.261 20.394 31.339 ;
     RECT  21.276 31.019 62.097 31.495 ;
     RECT  63.288 31.081 63.882 31.531 ;
     RECT  21.24 31.495 62.097 31.621 ;
     RECT  2.268 31.339 20.394 31.649 ;
     RECT  2.268 31.649 18.954 31.721 ;
     RECT  63.252 31.531 63.882 31.721 ;
     RECT  21.132 31.621 62.097 31.765 ;
     RECT  21.132 31.765 62.154 31.801 ;
     RECT  19.692 31.649 20.394 31.867 ;
     RECT  21.132 31.801 62.226 31.867 ;
     RECT  63.828 31.721 63.882 31.949 ;
     RECT  19.692 31.867 62.226 32.027 ;
     RECT  20.016 32.027 62.226 32.071 ;
     RECT  63.828 31.949 63.846 32.491 ;
     RECT  20.016 32.071 62.514 32.495 ;
     RECT  2.304 31.721 18.954 32.881 ;
     RECT  63.252 32.491 63.846 32.909 ;
     RECT  2.304 32.881 18.99 33.007 ;
     RECT  20.412 32.495 62.514 33.007 ;
     RECT  63.828 32.909 63.846 33.007 ;
     RECT  0.072 33.007 0.09 33.101 ;
     RECT  2.304 33.007 19.098 33.151 ;
     RECT  20.412 33.007 62.73 33.293 ;
     RECT  2.304 33.151 19.134 33.349 ;
     RECT  2.304 33.349 19.314 33.421 ;
     RECT  2.304 33.421 19.638 33.511 ;
     RECT  20.412 33.293 62.514 33.511 ;
     RECT  2.304 33.511 62.514 33.539 ;
     RECT  63.828 33.007 63.882 33.643 ;
     RECT  14.796 33.539 62.514 33.647 ;
     RECT  14.904 33.647 62.514 33.869 ;
     RECT  63.252 33.643 63.882 34.079 ;
     RECT  2.304 33.539 14.058 34.465 ;
     RECT  14.904 33.869 62.226 34.465 ;
     RECT  63.828 34.079 63.882 34.591 ;
     RECT  63.828 34.591 63.918 34.829 ;
     RECT  62.964 34.411 62.982 34.961 ;
     RECT  2.304 34.465 62.226 35.005 ;
     RECT  0.072 34.735 0.09 35.021 ;
     RECT  63.828 34.829 63.846 35.239 ;
     RECT  63.288 35.239 63.846 35.405 ;
     RECT  2.304 35.005 62.298 35.755 ;
     RECT  63.792 35.405 63.846 35.969 ;
     RECT  63.792 35.969 63.81 36.139 ;
     RECT  63.252 36.139 63.81 36.239 ;
     RECT  63.252 36.239 63.27 36.331 ;
     RECT  63.216 36.331 63.27 36.347 ;
     RECT  2.304 35.755 62.442 36.481 ;
     RECT  63.216 36.347 63.234 36.481 ;
     RECT  2.304 36.481 63.234 36.557 ;
     RECT  63.216 36.557 63.234 37.099 ;
     RECT  2.304 36.557 62.442 37.319 ;
     RECT  2.304 37.319 62.334 37.625 ;
     RECT  63.216 37.099 63.846 37.675 ;
     RECT  2.34 37.625 62.334 37.904 ;
     RECT  0.072 38.059 0.09 38.189 ;
     RECT  2.415 37.904 62.334 38.251 ;
     RECT  63.144 37.675 63.846 38.251 ;
     RECT  2.415 38.251 63.846 38.507 ;
     RECT  2.415 38.507 63.81 38.635 ;
     RECT  2.304 38.635 63.81 38.669 ;
     RECT  2.304 38.669 63.774 38.861 ;
     RECT  34.668 38.861 63.774 38.939 ;
     RECT  34.668 38.939 56.97 38.975 ;
     RECT  60.192 38.939 63.774 38.975 ;
     RECT  2.304 38.861 33.822 39.011 ;
     RECT  2.304 39.011 31.122 39.047 ;
     RECT  31.896 39.011 33.822 39.083 ;
     RECT  31.104 39.047 31.122 39.119 ;
     RECT  34.668 38.975 56.754 39.119 ;
     RECT  55.116 39.119 56.754 39.209 ;
     RECT  60.228 38.975 63.774 39.209 ;
     RECT  32.115 39.083 33.822 39.245 ;
     RECT  55.116 39.209 56.697 39.245 ;
     RECT  60.228 39.209 63.234 39.245 ;
     RECT  60.3 39.245 63.234 39.317 ;
     RECT  64.692 35.947 64.71 39.389 ;
     RECT  2.304 39.047 29.826 39.479 ;
     RECT  60.3 39.317 62.298 39.479 ;
     RECT  63.216 39.317 63.234 39.479 ;
     RECT  32.115 39.245 33.714 39.515 ;
     RECT  60.372 39.479 62.298 39.515 ;
     RECT  32.115 39.515 33.642 39.587 ;
     RECT  34.668 39.119 54.342 39.623 ;
     RECT  57.816 38.939 59.397 39.623 ;
     RECT  58.608 39.623 59.397 39.629 ;
     RECT  2.304 39.479 28.638 39.749 ;
     RECT  60.372 39.515 62.097 39.749 ;
     RECT  60.372 39.749 60.822 39.785 ;
     RECT  34.815 39.623 54.342 39.929 ;
     RECT  32.115 39.587 33.102 40.333 ;
     RECT  32.115 40.333 33.534 40.361 ;
     RECT  33.516 40.361 33.534 40.397 ;
     RECT  29.415 39.479 29.826 40.433 ;
     RECT  33.66 40.405 33.678 40.445 ;
     RECT  55.728 39.245 56.697 40.469 ;
     RECT  2.304 39.749 28.566 40.559 ;
     RECT  36.504 39.929 54.342 40.603 ;
     RECT  34.815 39.929 35.73 40.651 ;
     RECT  36.504 40.603 54.45 40.651 ;
     RECT  25.092 40.559 28.566 40.703 ;
     RECT  34.815 40.651 54.45 40.703 ;
     RECT  28.548 40.703 28.566 40.739 ;
     RECT  57.816 39.623 57.834 40.739 ;
     RECT  36.54 40.703 36.558 40.877 ;
     RECT  37.515 40.703 54.45 41.251 ;
     RECT  2.304 40.559 24.297 41.279 ;
     RECT  22.5 41.279 24.297 41.369 ;
     RECT  25.092 40.703 27.774 41.405 ;
     RECT  37.515 41.251 54.666 41.453 ;
     RECT  22.5 41.369 23.13 41.477 ;
     RECT  25.2 41.405 27.774 41.513 ;
     RECT  34.815 40.703 35.73 41.549 ;
     RECT  39.204 41.453 53.997 41.555 ;
     RECT  25.2 41.513 25.218 41.597 ;
     RECT  23.904 41.369 24.297 41.639 ;
     RECT  26.1 41.513 27.774 41.639 ;
     RECT  2.304 41.279 20.25 41.648 ;
     RECT  26.1 41.639 26.997 41.675 ;
     RECT  22.5 41.477 22.842 41.693 ;
     RECT  22.572 41.693 22.842 41.747 ;
     RECT  21.024 41.279 21.597 41.819 ;
     RECT  22.824 41.747 22.842 41.909 ;
     RECT  27.756 41.639 27.774 41.909 ;
     RECT  39.348 41.555 53.997 41.981 ;
     RECT  37.515 41.453 38.43 42.017 ;
     RECT  39.348 41.981 51.39 42.017 ;
     RECT  39.348 42.017 51.297 42.029 ;
     RECT  52.272 41.981 53.997 42.029 ;
     RECT  2.304 41.648 20.214 42.053 ;
     RECT  39.348 42.029 40.842 42.053 ;
     RECT  41.724 42.029 51.297 42.053 ;
     RECT  52.272 42.029 52.434 42.053 ;
     RECT  40.215 42.053 40.842 42.179 ;
     RECT  41.724 42.053 47.394 42.179 ;
     RECT  52.272 42.053 52.362 42.179 ;
     RECT  53.676 42.029 53.997 42.179 ;
     RECT  2.304 42.053 19.494 42.215 ;
     RECT  48.132 42.053 51.297 42.251 ;
     RECT  42.156 42.179 47.394 42.269 ;
     RECT  39.348 42.053 39.366 42.323 ;
     RECT  42.408 42.269 43.974 42.323 ;
     RECT  40.215 42.179 40.626 42.449 ;
     RECT  44.856 42.269 47.394 42.449 ;
     RECT  48.315 42.251 51.297 42.485 ;
     RECT  42.48 42.323 43.974 42.521 ;
     RECT  48.315 42.485 49.518 42.557 ;
     RECT  42.588 42.521 43.83 42.593 ;
     RECT  50.328 42.485 51.297 42.593 ;
     RECT  42.804 42.593 43.83 42.629 ;
     RECT  50.76 42.593 51.297 42.629 ;
     RECT  45.615 42.449 47.394 42.653 ;
     RECT  2.304 42.215 18.954 42.719 ;
     RECT  42.915 42.629 43.83 42.719 ;
     RECT  45.615 42.653 47.142 42.719 ;
     RECT  44.856 42.449 44.874 42.749 ;
     RECT  42.915 42.719 43.578 42.755 ;
     RECT  45.615 42.719 46.962 42.755 ;
     RECT  48.315 42.557 48.906 42.755 ;
     RECT  2.304 42.719 18.897 43.529 ;
     RECT  2.304 43.529 17.622 43.799 ;
     RECT  2.304 43.799 17.478 44.339 ;
     RECT  2.304 44.339 12.006 44.375 ;
     RECT  2.304 44.375 11.934 44.411 ;
     RECT  12.78 44.339 17.37 44.717 ;
     RECT  12.78 44.717 17.262 44.879 ;
     RECT  2.304 44.411 11.898 44.915 ;
     RECT  15.516 44.879 17.226 44.987 ;
     RECT  0.54 43.843 0.558 45.005 ;
     RECT  15.588 44.987 17.226 45.023 ;
     RECT  15.804 45.023 17.226 45.059 ;
     RECT  12.78 44.879 14.562 45.149 ;
     RECT  15.915 45.059 17.226 45.149 ;
     RECT  12.78 45.149 14.49 45.185 ;
     RECT  15.915 45.149 17.118 45.185 ;
     RECT  12.924 45.185 14.49 45.329 ;
     RECT  13.14 45.329 14.49 45.419 ;
     RECT  13.14 45.419 13.878 45.455 ;
     RECT  13.215 45.455 13.878 45.689 ;
     RECT  13.215 45.689 13.806 45.725 ;
     RECT  2.304 44.915 11.826 46.237 ;
     RECT  2.304 46.237 11.934 46.499 ;
     RECT  2.304 46.499 11.826 46.643 ;
     RECT  10.296 46.643 11.826 46.769 ;
     RECT  10.296 46.769 10.797 46.949 ;
     RECT  2.304 46.643 9.558 47.381 ;
     RECT  3.852 47.381 9.558 47.579 ;
     RECT  2.304 47.381 2.697 48.043 ;
     RECT  3.852 47.579 8.55 48.163 ;
     RECT  2.268 48.043 2.697 48.235 ;
     RECT  3.564 48.163 8.55 48.235 ;
     RECT  2.268 48.235 2.754 48.271 ;
     RECT  3.492 48.235 8.55 48.271 ;
     RECT  2.268 48.271 8.55 48.695 ;
     RECT  9.54 47.579 9.558 48.929 ;
     RECT  2.304 48.695 8.55 49.469 ;
     RECT  2.304 49.469 2.934 50.152 ;
     RECT  2.268 50.152 2.934 50.387 ;
     RECT  2.304 50.387 2.934 50.431 ;
     RECT  3.852 49.469 8.55 50.431 ;
     RECT  0.072 50.665 0.09 51.149 ;
     RECT  2.304 50.431 8.55 52.979 ;
     RECT  0.072 52.987 0.09 53.261 ;
     RECT  2.304 52.979 7.074 53.591 ;
     RECT  7.815 52.979 8.55 54.139 ;
     RECT  7.632 54.139 8.55 54.167 ;
     RECT  2.304 53.591 6.678 54.445 ;
     RECT  2.304 54.445 6.75 54.509 ;
     RECT  2.304 54.509 6.606 54.905 ;
     RECT  7.632 54.167 8.097 55.021 ;
     RECT  7.524 55.021 8.097 55.139 ;
     RECT  3.6 54.905 6.606 55.243 ;
     RECT  2.304 54.905 2.697 55.627 ;
     RECT  3.6 55.243 6.858 55.627 ;
     RECT  2.304 55.627 6.858 55.949 ;
     RECT  6.192 55.949 6.858 56.101 ;
     RECT  6.192 56.101 6.894 56.219 ;
     RECT  6.192 56.219 6.75 56.327 ;
     RECT  6.228 56.327 6.75 56.759 ;
     RECT  7.632 55.139 8.097 56.759 ;
     RECT  2.304 55.949 5.397 56.795 ;
     RECT  2.415 56.795 5.397 57.029 ;
     RECT  2.415 57.029 3.33 57.065 ;
     RECT  4.248 57.029 5.397 57.065 ;
     RECT  4.68 57.065 5.397 57.209 ;
     RECT  6.228 56.759 6.246 57.299 ;
     RECT  2.415 57.065 2.697 62.387 ;
     RECT  5.115 57.209 5.397 62.387 ;
     RECT  7.815 56.759 8.097 62.387 ;
     RECT  10.515 46.949 10.797 62.387 ;
     RECT  13.215 45.725 13.497 62.387 ;
     RECT  15.915 45.185 16.197 62.387 ;
     RECT  18.615 43.529 18.897 62.387 ;
     RECT  21.315 41.819 21.597 62.387 ;
     RECT  24.015 41.639 24.297 62.387 ;
     RECT  26.715 41.675 26.997 62.387 ;
     RECT  29.415 40.433 29.697 62.387 ;
     RECT  32.115 40.361 32.397 62.387 ;
     RECT  34.815 41.549 35.097 62.387 ;
     RECT  37.515 42.017 37.797 62.387 ;
     RECT  40.215 42.449 40.497 62.387 ;
     RECT  42.915 42.755 43.197 62.387 ;
     RECT  45.615 42.755 45.897 62.387 ;
     RECT  48.315 42.755 48.597 62.387 ;
     RECT  51.015 42.629 51.297 62.387 ;
     RECT  53.715 42.179 53.997 62.387 ;
     RECT  56.415 40.469 56.697 62.387 ;
     RECT  59.115 39.629 59.397 62.387 ;
     RECT  61.815 39.749 62.097 62.387 ;
     RECT  2.415 62.387 2.505 62.657 ;
     RECT  5.115 62.387 5.205 62.657 ;
     RECT  7.815 62.387 7.905 62.657 ;
     RECT  10.515 62.387 10.605 62.657 ;
     RECT  13.215 62.387 13.305 62.657 ;
     RECT  15.915 62.387 16.005 62.657 ;
     RECT  18.615 62.387 18.705 62.657 ;
     RECT  21.315 62.387 21.405 62.657 ;
     RECT  24.015 62.387 24.105 62.657 ;
     RECT  26.715 62.387 26.805 62.657 ;
     RECT  29.415 62.387 29.505 62.657 ;
     RECT  32.115 62.387 32.205 62.657 ;
     RECT  34.815 62.387 34.905 62.657 ;
     RECT  37.515 62.387 37.605 62.657 ;
     RECT  40.215 62.387 40.305 62.657 ;
     RECT  42.915 62.387 43.005 62.657 ;
     RECT  45.615 62.387 45.705 62.657 ;
     RECT  48.315 62.387 48.405 62.657 ;
     RECT  51.015 62.387 51.105 62.657 ;
     RECT  53.715 62.387 53.805 62.657 ;
     RECT  56.415 62.387 56.505 62.657 ;
     RECT  59.115 62.387 59.205 62.657 ;
     RECT  61.815 62.387 61.905 62.657 ;
    LAYER M4 ;
     RECT  0.06 7.92 2.408 56.904 ;
     RECT  2.408 2.148 2.512 62.652 ;
     RECT  2.512 2.418 2.704 62.382 ;
     RECT  2.704 13.152 2.765 14.856 ;
     RECT  2.704 19.296 2.765 33.288 ;
     RECT  2.704 48.24 2.765 48.504 ;
     RECT  2.704 52.272 2.765 54.408 ;
     RECT  2.704 9.072 2.837 11.208 ;
     RECT  2.704 35.184 2.873 42.6 ;
     RECT  2.837 10.704 2.909 11.208 ;
     RECT  2.837 9.072 2.945 9.576 ;
     RECT  2.765 52.272 3.017 52.296 ;
     RECT  2.909 10.704 3.089 10.728 ;
     RECT  2.765 54.144 3.197 54.408 ;
     RECT  2.704 7.92 3.34 7.944 ;
     RECT  2.704 55.632 3.341 56.52 ;
     RECT  2.704 44.928 3.395 46.488 ;
     RECT  2.945 9.072 3.697 9.096 ;
     RECT  3.697 7.968 3.737 9.096 ;
     RECT  2.704 43.776 3.841 43.8 ;
     RECT  2.765 19.296 3.877 29.832 ;
     RECT  2.765 30.816 3.877 33.288 ;
     RECT  3.877 19.296 3.925 33.288 ;
     RECT  3.197 54.144 3.961 54.168 ;
     RECT  2.704 18.192 3.98 18.216 ;
     RECT  3.395 44.928 3.985 45.672 ;
     RECT  2.765 48.48 3.985 48.504 ;
     RECT  3.98 18.144 4.021 18.216 ;
     RECT  3.925 19.296 4.021 34.008 ;
     RECT  2.704 50.832 4.117 50.856 ;
     RECT  2.873 35.232 4.165 42.6 ;
     RECT  3.841 43.584 4.165 43.8 ;
     RECT  2.765 14.208 4.201 14.856 ;
     RECT  2.765 13.152 4.237 13.176 ;
     RECT  3.841 46.848 4.261 46.872 ;
     RECT  3.985 48.384 4.261 48.504 ;
     RECT  4.165 35.232 4.309 43.8 ;
     RECT  2.704 16.56 4.364 16.584 ;
     RECT  4.021 18.144 4.364 34.008 ;
     RECT  3.985 44.88 4.417 45.672 ;
     RECT  4.261 46.848 4.417 48.504 ;
     RECT  4.021 10.944 4.501 10.968 ;
     RECT  4.309 35.232 4.597 43.896 ;
     RECT  4.417 44.88 4.597 48.504 ;
     RECT  4.201 14.208 4.705 15.096 ;
     RECT  4.364 16.56 4.705 34.008 ;
     RECT  4.705 14.208 4.849 34.008 ;
     RECT  4.597 35.232 4.849 48.504 ;
     RECT  4.117 50.16 4.849 50.856 ;
     RECT  4.501 10.224 4.913 10.968 ;
     RECT  3.341 55.632 4.957 55.656 ;
     RECT  3.737 7.968 4.993 8.856 ;
     RECT  4.993 7.968 5.108 9.096 ;
     RECT  4.913 10.224 5.108 11.4 ;
     RECT  4.237 13.056 5.108 13.176 ;
     RECT  4.849 14.208 5.108 48.504 ;
     RECT  4.849 50.16 5.108 51.336 ;
     RECT  4.957 53.52 5.108 53.544 ;
     RECT  4.957 54.864 5.108 55.656 ;
     RECT  5.108 2.148 5.212 62.652 ;
     RECT  5.212 2.418 5.404 62.382 ;
     RECT  5.404 50.16 5.465 50.568 ;
     RECT  5.404 14.208 5.537 14.856 ;
     RECT  5.404 39.216 5.555 47.88 ;
     RECT  5.404 51.792 5.555 51.816 ;
     RECT  5.404 53.04 5.581 55.32 ;
     RECT  5.555 39.264 5.645 47.4 ;
     RECT  5.645 39.264 5.681 46.584 ;
     RECT  5.581 53.04 5.699 55.272 ;
     RECT  5.681 39.264 5.789 46.344 ;
     RECT  5.404 15.984 5.795 38.232 ;
     RECT  5.789 43.824 5.825 46.344 ;
     RECT  5.699 53.52 5.861 55.272 ;
     RECT  5.795 15.984 5.897 18.168 ;
     RECT  5.537 14.304 6.005 14.856 ;
     RECT  5.404 10.944 6.275 10.968 ;
     RECT  5.404 12.192 6.38 13.08 ;
     RECT  6.38 12.192 6.437 13.32 ;
     RECT  6.437 12.48 6.467 13.32 ;
     RECT  5.404 9.072 6.505 9.96 ;
     RECT  6.505 9.072 6.517 10.2 ;
     RECT  5.897 15.984 6.517 17.64 ;
     RECT  6.467 12.48 6.563 13.08 ;
     RECT  5.825 43.824 6.581 46.248 ;
     RECT  5.795 19.2 6.613 38.232 ;
     RECT  5.789 39.264 6.613 42.84 ;
     RECT  6.005 14.304 6.653 14.328 ;
     RECT  6.517 15.36 6.659 17.64 ;
     RECT  5.861 53.568 6.721 55.272 ;
     RECT  6.721 53.568 6.733 55.848 ;
     RECT  6.613 19.2 6.757 42.84 ;
     RECT  6.581 43.824 6.757 45.816 ;
     RECT  6.757 19.2 6.833 45.816 ;
     RECT  5.465 50.16 6.86 50.184 ;
     RECT  6.86 49.44 6.901 50.184 ;
     RECT  6.901 49.44 6.973 50.712 ;
     RECT  6.901 47.856 7.009 47.88 ;
     RECT  6.973 49.44 7.045 51.336 ;
     RECT  6.517 8.16 7.285 10.2 ;
     RECT  7.009 47.328 7.549 47.88 ;
     RECT  6.733 54.144 7.657 55.848 ;
     RECT  7.285 8.16 7.808 10.872 ;
     RECT  6.563 12.48 7.808 12.504 ;
     RECT  6.659 16.032 7.808 17.64 ;
     RECT  6.833 19.2 7.808 43.896 ;
     RECT  6.833 44.976 7.808 45.816 ;
     RECT  7.549 47.328 7.808 47.928 ;
     RECT  7.045 49.44 7.808 51.624 ;
     RECT  7.657 54.144 7.808 55.992 ;
     RECT  7.808 2.148 7.912 62.652 ;
     RECT  7.912 2.418 8.104 62.382 ;
     RECT  8.104 8.112 8.165 8.52 ;
     RECT  8.104 30.432 8.165 43.128 ;
     RECT  8.104 44.976 8.237 46.632 ;
     RECT  8.104 14.208 8.243 14.232 ;
     RECT  8.104 24.096 8.243 29.352 ;
     RECT  8.104 15.36 8.245 22.776 ;
     RECT  8.237 45.12 8.245 46.632 ;
     RECT  8.245 16.032 8.273 22.776 ;
     RECT  8.104 51.888 8.339 51.912 ;
     RECT  8.165 40.848 8.381 43.128 ;
     RECT  8.381 40.944 8.489 43.128 ;
     RECT  8.489 40.944 8.531 42.792 ;
     RECT  8.104 55.968 8.579 55.992 ;
     RECT  8.273 21.936 8.597 22.776 ;
     RECT  8.243 24.624 8.597 29.352 ;
     RECT  8.245 45.792 8.597 46.632 ;
     RECT  8.273 16.032 8.633 20.952 ;
     RECT  8.597 22.032 8.669 22.776 ;
     RECT  8.597 24.672 8.741 29.352 ;
     RECT  8.104 3.648 8.819 3.768 ;
     RECT  8.165 8.112 8.819 8.136 ;
     RECT  8.633 17.616 9.029 20.952 ;
     RECT  8.104 50.736 9.155 50.76 ;
     RECT  9.029 17.616 9.173 19.368 ;
     RECT  8.633 16.032 9.281 16.632 ;
     RECT  9.205 0.576 9.289 0.6 ;
     RECT  8.741 25.056 9.313 29.352 ;
     RECT  8.165 30.432 9.313 39.864 ;
     RECT  9.313 25.056 9.389 39.864 ;
     RECT  8.531 40.944 9.461 40.968 ;
     RECT  9.389 25.68 9.532 39.864 ;
     RECT  9.241 23.664 9.781 23.688 ;
     RECT  8.669 22.368 9.817 22.392 ;
     RECT  8.531 42 9.817 42.792 ;
     RECT  9.173 17.616 9.997 17.928 ;
     RECT  9.173 18.912 10.177 19.368 ;
     RECT  9.029 20.688 10.177 20.952 ;
     RECT  9.997 17.52 10.249 17.928 ;
     RECT  10.177 18.912 10.249 20.952 ;
     RECT  9.817 22.368 10.249 22.488 ;
     RECT  9.281 16.032 10.357 16.056 ;
     RECT  10.249 17.424 10.357 17.928 ;
     RECT  10.249 18.912 10.357 22.488 ;
     RECT  9.781 23.52 10.357 23.688 ;
     RECT  9.565 44.736 10.357 44.76 ;
     RECT  9.532 38.4 10.429 39.864 ;
     RECT  9.817 41.52 10.501 42.792 ;
     RECT  8.819 3.648 10.508 3.672 ;
     RECT  10.357 16.032 10.508 23.688 ;
     RECT  9.532 25.68 10.508 37.08 ;
     RECT  10.429 38.4 10.508 40.152 ;
     RECT  10.501 41.52 10.508 43.08 ;
     RECT  10.357 44.736 10.508 45.288 ;
     RECT  8.597 46.368 10.508 46.632 ;
     RECT  10.508 2.148 10.612 62.652 ;
     RECT  10.612 2.418 10.804 62.382 ;
     RECT  10.804 21.936 10.829 26.328 ;
     RECT  10.829 21.984 10.865 26.328 ;
     RECT  10.804 27.504 10.865 31.944 ;
     RECT  10.804 33.072 10.865 33.624 ;
     RECT  10.804 46.608 11.153 46.632 ;
     RECT  10.865 21.984 11.189 26.04 ;
     RECT  11.189 21.984 11.333 22.536 ;
     RECT  10.804 42 11.477 45.288 ;
     RECT  10.804 38.304 11.513 40.392 ;
     RECT  11.513 38.304 11.585 39.144 ;
     RECT  11.189 23.52 11.603 26.04 ;
     RECT  11.477 43.92 11.657 45.288 ;
     RECT  11.585 38.304 11.693 38.808 ;
     RECT  11.513 40.128 11.693 40.392 ;
     RECT  11.657 44.736 11.837 45.288 ;
     RECT  11.837 44.736 11.909 44.76 ;
     RECT  10.865 33.264 11.977 33.624 ;
     RECT  11.693 40.32 11.977 40.392 ;
     RECT  11.477 42 11.977 42.936 ;
     RECT  10.804 15.984 11.981 20.664 ;
     RECT  11.603 23.52 11.987 25.416 ;
     RECT  11.977 40.32 12.035 42.936 ;
     RECT  10.865 27.504 12.121 30.12 ;
     RECT  12.035 40.32 12.125 42.312 ;
     RECT  10.804 35.76 12.157 36.888 ;
     RECT  11.333 21.984 12.337 22.488 ;
     RECT  11.987 23.52 12.337 23.688 ;
     RECT  11.977 33.168 12.337 33.624 ;
     RECT  12.157 34.896 12.337 36.888 ;
     RECT  12.337 33.168 12.373 36.888 ;
     RECT  12.373 33.12 12.445 36.888 ;
     RECT  12.121 26.544 12.481 30.12 ;
     RECT  12.481 26.544 12.553 30.168 ;
     RECT  10.865 31.344 12.553 31.944 ;
     RECT  11.693 38.592 12.697 38.808 ;
     RECT  12.445 33.12 12.877 37.128 ;
     RECT  12.697 38.592 12.877 39.24 ;
     RECT  11.981 15.984 12.949 20.376 ;
     RECT  12.769 44.448 13.045 44.472 ;
     RECT  10.804 3.648 13.208 3.672 ;
     RECT  12.949 15.984 13.208 20.424 ;
     RECT  12.337 21.984 13.208 23.688 ;
     RECT  11.987 24.96 13.208 25.416 ;
     RECT  12.553 26.544 13.208 31.944 ;
     RECT  12.877 33.12 13.208 39.24 ;
     RECT  12.125 41.088 13.208 42.312 ;
     RECT  12.553 43.344 13.208 43.368 ;
     RECT  13.045 44.448 13.208 45.144 ;
     RECT  13.208 2.148 13.312 62.652 ;
     RECT  13.312 2.418 13.504 62.382 ;
     RECT  13.504 3.552 13.601 3.672 ;
     RECT  13.504 26.832 13.745 27.96 ;
     RECT  13.504 17.088 13.781 25.176 ;
     RECT  13.504 38.688 13.852 44.664 ;
     RECT  13.504 34.752 14.069 35.256 ;
     RECT  14.069 34.752 14.177 34.824 ;
     RECT  13.781 17.088 14.213 20.136 ;
     RECT  14.213 17.088 14.285 19.896 ;
     RECT  13.745 26.832 14.357 27.912 ;
     RECT  13.852 43.344 14.465 44.664 ;
     RECT  13.504 36.528 14.497 37.656 ;
     RECT  14.285 17.088 14.537 19.656 ;
     RECT  13.781 21.12 14.713 25.176 ;
     RECT  14.465 43.344 14.789 44.136 ;
     RECT  13.601 3.552 14.821 3.576 ;
     RECT  13.504 28.944 14.821 29.832 ;
     RECT  13.504 31.44 14.821 33.288 ;
     RECT  14.821 3.552 14.861 3.672 ;
     RECT  14.78 34.56 14.867 34.584 ;
     RECT  13.852 38.688 14.867 42.312 ;
     RECT  14.713 21.12 14.929 25.656 ;
     RECT  14.357 26.832 14.929 27.72 ;
     RECT  14.821 28.944 15.181 33.288 ;
     RECT  14.497 36 15.325 37.656 ;
     RECT  14.867 38.688 15.325 41.928 ;
     RECT  14.929 21.12 15.349 27.72 ;
     RECT  15.181 28.944 15.349 33.864 ;
     RECT  14.789 43.344 15.505 43.896 ;
     RECT  14.861 3.648 15.908 3.672 ;
     RECT  14.537 17.616 15.908 19.656 ;
     RECT  15.349 21.12 15.908 33.864 ;
     RECT  15.325 36 15.908 41.928 ;
     RECT  15.505 43.2 15.908 43.896 ;
     RECT  15.908 2.148 16.012 62.652 ;
     RECT  16.012 2.418 16.204 62.382 ;
     RECT  16.204 29.52 16.373 33.864 ;
     RECT  16.204 16.8 16.445 28.008 ;
     RECT  16.204 44.64 16.547 44.664 ;
     RECT  16.445 19.632 16.589 28.008 ;
     RECT  16.204 39.024 16.661 39.816 ;
     RECT  16.204 35.28 16.913 37.896 ;
     RECT  16.913 35.568 17.027 37.896 ;
     RECT  16.373 29.52 17.129 33.72 ;
     RECT  16.445 16.8 17.165 18.552 ;
     RECT  16.589 19.632 17.201 20.184 ;
     RECT  16.204 41.472 17.269 42.744 ;
     RECT  16.589 21.216 17.273 28.008 ;
     RECT  17.027 35.568 17.309 35.592 ;
     RECT  17.269 41.472 17.345 42.792 ;
     RECT  17.129 32.928 17.453 33.72 ;
     RECT  17.273 21.216 17.507 27.24 ;
     RECT  17.345 41.664 17.525 42.792 ;
     RECT  16.661 39.024 17.629 39.624 ;
     RECT  17.507 21.216 17.653 25.848 ;
     RECT  16.204 3.648 17.893 3.672 ;
     RECT  17.629 39.024 17.953 39.768 ;
     RECT  17.027 36.864 18.097 37.896 ;
     RECT  17.129 30.816 18.133 31.848 ;
     RECT  17.665 28.992 18.169 29.016 ;
     RECT  18.133 30.048 18.169 31.848 ;
     RECT  17.917 34.944 18.169 34.968 ;
     RECT  18.169 28.992 18.229 31.848 ;
     RECT  17.453 32.928 18.229 33.672 ;
     RECT  18.097 36.816 18.241 37.896 ;
     RECT  17.953 39.024 18.313 40.44 ;
     RECT  17.521 19.104 18.449 19.512 ;
     RECT  17.653 20.544 18.449 25.848 ;
     RECT  17.507 27.216 18.469 27.24 ;
     RECT  17.893 3.648 18.608 3.864 ;
     RECT  17.165 16.8 18.608 16.824 ;
     RECT  17.165 17.952 18.608 17.976 ;
     RECT  18.449 19.104 18.608 25.848 ;
     RECT  18.469 27.216 18.608 28.008 ;
     RECT  18.229 28.992 18.608 33.672 ;
     RECT  18.169 34.896 18.608 34.968 ;
     RECT  18.241 36.048 18.608 37.896 ;
     RECT  18.313 38.976 18.608 40.44 ;
     RECT  17.525 41.664 18.608 42.744 ;
     RECT  18.608 2.148 18.712 62.652 ;
     RECT  18.712 2.418 18.904 62.382 ;
     RECT  18.904 22.464 18.929 22.584 ;
     RECT  18.904 38.64 18.929 40.44 ;
     RECT  18.929 40.128 18.965 40.44 ;
     RECT  18.904 33.264 19.001 34.92 ;
     RECT  18.929 22.56 19.037 22.584 ;
     RECT  18.965 40.416 19.037 40.44 ;
     RECT  18.904 24.96 19.253 26.712 ;
     RECT  18.904 41.424 19.253 42.024 ;
     RECT  19.001 33.36 19.325 34.92 ;
     RECT  18.904 30.048 19.793 30.168 ;
     RECT  18.904 28.992 19.829 29.064 ;
     RECT  18.904 27.984 19.893 28.008 ;
     RECT  19.253 41.424 19.897 41.976 ;
     RECT  19.829 29.04 19.969 29.064 ;
     RECT  19.897 40.992 20.045 41.976 ;
     RECT  18.904 20.928 20.099 21.144 ;
     RECT  20.053 22.944 20.14 23.352 ;
     RECT  18.904 31.344 20.153 31.944 ;
     RECT  19.253 24.96 20.221 26.664 ;
     RECT  19.325 33.648 20.245 34.92 ;
     RECT  20.221 24.96 20.297 27.336 ;
     RECT  18.929 38.64 20.492 39.048 ;
     RECT  20.245 33.648 20.533 35.448 ;
     RECT  20.492 38.64 20.876 40.008 ;
     RECT  20.045 40.992 20.876 41.64 ;
     RECT  20.876 38.64 20.977 41.64 ;
     RECT  20.153 31.872 21.049 31.944 ;
     RECT  20.533 33.024 21.049 35.448 ;
     RECT  20.365 37.056 21.085 37.08 ;
     RECT  20.977 38.208 21.085 41.64 ;
     RECT  21.085 37.056 21.157 41.64 ;
     RECT  18.904 3.648 21.308 3.864 ;
     RECT  20.099 20.928 21.308 20.952 ;
     RECT  20.14 23.328 21.308 23.352 ;
     RECT  20.297 24.96 21.308 25.944 ;
     RECT  20.297 27.312 21.308 27.336 ;
     RECT  19.969 29.04 21.308 29.688 ;
     RECT  21.049 31.872 21.308 35.448 ;
     RECT  21.157 37.056 21.308 41.688 ;
     RECT  21.308 2.148 21.412 62.652 ;
     RECT  21.412 2.418 21.604 62.382 ;
     RECT  21.604 28.992 21.737 29.592 ;
     RECT  21.604 30.576 21.809 32.28 ;
     RECT  21.604 22.224 22.277 26.712 ;
     RECT  22.277 22.224 22.313 23.352 ;
     RECT  22.313 22.224 22.349 22.248 ;
     RECT  21.604 39.888 22.529 41.688 ;
     RECT  21.604 3.648 22.565 4.152 ;
     RECT  21.604 36.048 22.597 36.072 ;
     RECT  22.277 24.48 22.633 26.712 ;
     RECT  22.633 24.48 22.705 27.384 ;
     RECT  21.604 37.056 22.741 37.08 ;
     RECT  22.633 38.208 22.741 38.232 ;
     RECT  21.604 33.84 22.748 35.016 ;
     RECT  22.597 36 22.748 36.072 ;
     RECT  21.604 20.928 22.777 20.952 ;
     RECT  22.529 39.888 22.777 41.448 ;
     RECT  21.809 31.872 22.789 32.28 ;
     RECT  22.748 33.84 22.789 36.072 ;
     RECT  22.741 37.056 22.789 38.232 ;
     RECT  22.777 20.832 22.817 20.952 ;
     RECT  22.705 24.48 22.817 27.912 ;
     RECT  22.817 24.624 22.844 27.912 ;
     RECT  21.737 29.472 22.844 29.592 ;
     RECT  21.809 30.576 22.921 30.6 ;
     RECT  22.789 31.872 22.921 38.232 ;
     RECT  22.844 24.624 23.237 29.592 ;
     RECT  22.921 30.576 23.237 38.232 ;
     RECT  23.237 24.624 23.857 38.232 ;
     RECT  23.857 24.624 23.893 38.424 ;
     RECT  22.777 39.84 23.893 41.448 ;
     RECT  23.461 1.728 24.008 1.752 ;
     RECT  22.565 3.84 24.008 4.152 ;
     RECT  22.817 20.832 24.008 20.856 ;
     RECT  22.313 23.328 24.008 23.352 ;
     RECT  23.893 24.624 24.008 41.448 ;
     RECT  24.008 1.728 24.112 62.652 ;
     RECT  24.112 1.728 24.131 62.382 ;
     RECT  24.131 2.418 24.304 62.382 ;
     RECT  24.304 23.904 24.401 27.384 ;
     RECT  24.401 26.304 24.803 27.384 ;
     RECT  24.304 22.656 24.941 22.68 ;
     RECT  25.081 0.576 25.165 0.6 ;
     RECT  24.304 4.512 25.273 4.536 ;
     RECT  24.304 31.2 25.297 36.648 ;
     RECT  24.401 23.904 25.301 25.032 ;
     RECT  24.304 37.68 25.331 41.592 ;
     RECT  25.297 30.816 25.333 36.648 ;
     RECT  24.304 20.688 25.405 21.672 ;
     RECT  24.304 28.416 25.405 29.352 ;
     RECT  25.405 20.592 25.445 21.672 ;
     RECT  25.333 30.816 25.697 37.08 ;
     RECT  25.405 28.416 25.765 29.592 ;
     RECT  24.803 26.352 25.837 27.384 ;
     RECT  25.765 28.416 25.837 29.832 ;
     RECT  25.837 26.352 25.909 29.832 ;
     RECT  25.909 26.064 26.017 29.832 ;
     RECT  25.331 38.064 26.045 41.592 ;
     RECT  25.301 24.336 26.161 25.032 ;
     RECT  26.017 26.016 26.161 29.832 ;
     RECT  25.697 33.888 26.305 37.08 ;
     RECT  26.045 38.064 26.305 41.64 ;
     RECT  26.161 24.336 26.449 29.832 ;
     RECT  25.697 30.816 26.449 32.568 ;
     RECT  25.445 20.592 26.708 20.616 ;
     RECT  25.445 21.648 26.708 21.672 ;
     RECT  25.945 22.8 26.708 22.824 ;
     RECT  26.449 24.336 26.708 32.568 ;
     RECT  26.305 33.888 26.708 41.64 ;
     RECT  26.708 2.148 26.812 62.652 ;
     RECT  26.812 2.418 27.004 62.382 ;
     RECT  27.004 24 27.821 40.392 ;
     RECT  27.821 26.064 27.965 40.392 ;
     RECT  27.965 26.064 28.145 39.72 ;
     RECT  27.821 24 28.181 24.936 ;
     RECT  28.181 24.912 28.969 24.936 ;
     RECT  28.145 26.064 28.969 38.76 ;
     RECT  28.969 24.912 29.185 38.76 ;
     RECT  27.004 20.592 29.408 20.616 ;
     RECT  29.185 24.72 29.408 38.76 ;
     RECT  29.408 2.148 29.512 62.652 ;
     RECT  29.512 2.418 29.704 62.382 ;
     RECT  29.704 20.592 30.269 38.424 ;
     RECT  30.269 20.592 30.515 27.48 ;
     RECT  30.515 21.12 30.557 27.48 ;
     RECT  30.557 21.648 30.563 27.48 ;
     RECT  30.563 22.512 30.601 27.48 ;
     RECT  30.601 24.624 30.845 27.48 ;
     RECT  30.269 28.464 30.917 38.424 ;
     RECT  30.917 36.288 31.057 38.424 ;
     RECT  30.845 24.672 31.309 27.48 ;
     RECT  30.917 28.464 31.309 35.208 ;
     RECT  31.057 36.288 31.309 38.568 ;
     RECT  31.309 24.672 31.921 35.208 ;
     RECT  31.309 36.288 31.921 38.808 ;
     RECT  29.704 3.312 32.108 3.336 ;
     RECT  30.601 22.512 32.108 23.352 ;
     RECT  31.921 24.384 32.108 38.808 ;
     RECT  32.108 2.148 32.212 62.652 ;
     RECT  32.212 2.418 32.404 62.382 ;
     RECT  31.909 0.096 32.435 0.12 ;
     RECT  32.404 22.464 33.397 36.936 ;
     RECT  32.404 38.016 33.509 38.808 ;
     RECT  33.509 38.16 33.577 38.808 ;
     RECT  33.505 40.368 33.649 40.392 ;
     RECT  33.577 38.16 33.793 38.856 ;
     RECT  33.505 20.304 33.973 20.328 ;
     RECT  33.973 20.304 34.369 21.192 ;
     RECT  33.397 22.32 34.369 36.936 ;
     RECT  34.369 20.304 34.765 36.936 ;
     RECT  32.404 3.312 34.808 3.336 ;
     RECT  34.765 20.304 34.808 37.08 ;
     RECT  33.793 38.16 34.808 39.24 ;
     RECT  33.649 40.368 34.808 40.44 ;
     RECT  34.808 2.148 34.912 62.652 ;
     RECT  34.912 2.418 35.104 62.382 ;
     RECT  35.104 26.304 35.237 40.68 ;
     RECT  35.104 20.304 35.267 23.112 ;
     RECT  35.237 26.304 35.273 37.08 ;
     RECT  35.267 20.304 36.169 23.064 ;
     RECT  35.104 24.192 36.277 25.224 ;
     RECT  35.273 26.304 36.277 36.984 ;
     RECT  35.237 38.064 36.277 40.68 ;
     RECT  36.169 20.064 36.425 23.064 ;
     RECT  36.277 24.192 36.529 40.68 ;
     RECT  36.425 20.112 36.925 23.064 ;
     RECT  36.529 24.192 36.925 40.872 ;
     RECT  35.104 3.312 37.508 3.336 ;
     RECT  36.925 20.112 37.508 40.872 ;
     RECT  37.508 2.148 37.612 62.652 ;
     RECT  37.612 2.418 37.804 62.382 ;
     RECT  37.804 19.008 38.965 40.872 ;
     RECT  38.965 19.008 38.977 40.968 ;
     RECT  38.977 19.008 39.193 41.448 ;
     RECT  39.193 19.008 39.337 41.544 ;
     RECT  39.781 17.664 39.841 17.688 ;
     RECT  39.337 18.768 39.841 41.544 ;
     RECT  37.804 3.312 40.208 3.336 ;
     RECT  39.841 17.664 40.208 41.544 ;
     RECT  40.208 2.148 40.312 62.652 ;
     RECT  40.312 2.418 40.504 62.382 ;
     RECT  40.504 17.904 41.893 42.744 ;
     RECT  41.893 17.568 42.037 42.744 ;
     RECT  40.504 3.312 42.145 3.336 ;
     RECT  42.217 0.576 42.467 0.6 ;
     RECT  42.037 17.424 42.469 42.744 ;
     RECT  41.749 1.728 42.908 1.752 ;
     RECT  42.145 3.312 42.908 4.152 ;
     RECT  42.469 17.184 42.908 42.744 ;
     RECT  42.908 1.728 43.012 62.652 ;
     RECT  43.012 1.728 43.204 62.382 ;
     RECT  43.204 3.312 44.588 4.152 ;
     RECT  43.204 1.728 45.203 1.752 ;
     RECT  44.588 3.168 45.608 4.152 ;
     RECT  43.204 17.136 45.608 42.744 ;
     RECT  45.608 2.148 45.712 62.652 ;
     RECT  45.712 2.418 45.904 62.382 ;
     RECT  45.904 3.6 46.897 3.624 ;
     RECT  46.897 3.408 46.937 3.624 ;
     RECT  45.904 17.136 46.973 42.744 ;
     RECT  46.973 17.136 48.181 42.648 ;
     RECT  46.937 3.408 48.308 3.432 ;
     RECT  48.181 16.512 48.308 42.648 ;
     RECT  48.308 2.148 48.412 62.652 ;
     RECT  45.701 0.576 48.529 0.6 ;
     RECT  48.412 2.148 48.604 62.382 ;
     RECT  48.604 17.328 49.493 42.024 ;
     RECT  49.493 17.376 49.601 42.024 ;
     RECT  49.601 17.952 49.633 42.024 ;
     RECT  49.633 17.952 49.669 42.12 ;
     RECT  49.669 17.952 49.817 42.216 ;
     RECT  49.817 18.048 49.925 42.216 ;
     RECT  48.604 4.224 50.137 4.248 ;
     RECT  49.273 1.728 51.008 1.752 ;
     RECT  50.137 3.408 51.008 4.248 ;
     RECT  49.925 18.048 51.008 42.12 ;
     RECT  51.008 1.728 51.112 62.652 ;
     RECT  51.112 1.728 51.265 62.382 ;
     RECT  51.265 2.418 51.304 62.382 ;
     RECT  51.304 18.96 51.977 42.024 ;
     RECT  51.937 0.576 52.259 0.6 ;
     RECT  51.977 20.064 52.337 42.024 ;
     RECT  51.977 18.96 52.697 18.984 ;
     RECT  51.304 4.224 52.873 4.248 ;
     RECT  52.657 1.728 53.708 1.752 ;
     RECT  52.873 3.36 53.708 4.248 ;
     RECT  52.337 20.352 53.708 42.024 ;
     RECT  53.708 1.728 53.812 62.652 ;
     RECT  53.812 1.728 53.987 62.382 ;
     RECT  53.987 2.418 54.004 62.382 ;
     RECT  54.004 20.688 54.569 39.624 ;
     RECT  54.004 41.424 54.677 41.448 ;
     RECT  54.745 0.576 54.995 0.6 ;
     RECT  54.004 3.408 55.187 4.536 ;
     RECT  54.569 20.688 55.397 28.008 ;
     RECT  54.569 29.232 55.621 39.624 ;
     RECT  55.429 1.728 56.408 1.752 ;
     RECT  55.187 3.408 56.408 4.248 ;
     RECT  55.397 20.688 56.408 23.976 ;
     RECT  55.397 25.104 56.408 28.008 ;
     RECT  55.621 29.04 56.408 39.624 ;
     RECT  56.408 1.728 56.512 62.652 ;
     RECT  56.512 1.728 56.704 62.382 ;
     RECT  56.704 1.728 56.771 1.752 ;
     RECT  56.704 30.768 56.819 32.376 ;
     RECT  56.704 35.904 57.011 38.424 ;
     RECT  57.011 38.16 57.125 38.424 ;
     RECT  56.819 30.768 57.161 30.888 ;
     RECT  56.704 23.808 57.305 23.928 ;
     RECT  56.704 25.68 57.34 28.008 ;
     RECT  57.34 26.064 57.349 28.008 ;
     RECT  57.305 23.808 57.413 23.832 ;
     RECT  57.685 3.168 57.772 3.192 ;
     RECT  57.349 26.256 57.773 28.008 ;
     RECT  57.733 0.576 57.817 0.6 ;
     RECT  57.011 35.904 57.845 36.984 ;
     RECT  56.704 33.552 57.989 34.776 ;
     RECT  57.845 36.24 57.989 36.984 ;
     RECT  57.773 26.256 58.025 27.72 ;
     RECT  58.025 26.64 58.133 27.72 ;
     RECT  57.125 38.16 58.165 38.184 ;
     RECT  57.161 30.768 58.201 30.792 ;
     RECT  58.237 1.728 58.355 1.752 ;
     RECT  56.819 32.352 58.561 32.376 ;
     RECT  57.989 33.552 58.561 33.576 ;
     RECT  56.704 4.224 58.693 4.248 ;
     RECT  56.704 29.28 58.885 29.688 ;
     RECT  58.201 30.768 58.885 31.128 ;
     RECT  58.561 32.352 58.885 33.576 ;
     RECT  58.849 0.576 58.933 0.6 ;
     RECT  57.989 34.752 59.065 34.776 ;
     RECT  57.989 36.24 59.065 36.552 ;
     RECT  58.693 3.696 59.108 4.248 ;
     RECT  58.133 26.784 59.108 27.72 ;
     RECT  58.885 29.28 59.108 33.576 ;
     RECT  59.065 34.752 59.108 36.552 ;
     RECT  58.165 37.632 59.108 38.184 ;
     RECT  56.704 39.6 59.108 39.624 ;
     RECT  59.108 2.148 59.212 62.652 ;
     RECT  59.212 2.148 59.353 62.382 ;
     RECT  59.353 1.728 59.404 62.382 ;
     RECT  59.404 26.784 59.465 26.856 ;
     RECT  59.404 38.16 59.465 38.184 ;
     RECT  59.404 1.728 59.507 1.752 ;
     RECT  59.404 32.736 60.041 32.76 ;
     RECT  59.404 35.424 60.041 35.448 ;
     RECT  59.404 30.288 60.113 30.312 ;
     RECT  60.389 0.576 60.473 0.6 ;
     RECT  59.465 26.832 60.473 26.856 ;
     RECT  60.973 30.336 61.808 30.36 ;
     RECT  61.585 36.816 61.808 36.84 ;
     RECT  61.808 2.148 61.912 62.652 ;
     RECT  61.912 2.418 62.104 62.382 ;
     RECT  62.104 32.688 62.129 36.84 ;
     RECT  62.129 32.688 63.133 36.744 ;
     RECT  62.104 38.256 63.133 38.28 ;
     RECT  62.104 26.544 63.241 27.528 ;
     RECT  62.104 28.848 63.241 29.832 ;
     RECT  62.104 30.96 63.241 30.984 ;
     RECT  63.133 32.688 63.241 38.28 ;
     RECT  63.241 26.544 63.277 29.832 ;
     RECT  63.241 30.96 63.277 38.472 ;
     RECT  63.277 26.544 63.817 38.472 ;
     RECT  63.817 26.352 64.764 38.472 ;
    LAYER M5 ;
     RECT  32.4 0.016 32.424 0.085 ;
     RECT  31.92 0.085 32.424 0.131 ;
     RECT  9.216 0.016 9.24 0.611 ;
     RECT  25.104 0.016 25.128 0.611 ;
     RECT  41.808 0.016 43.032 0.611 ;
     RECT  44.016 0.016 45.768 0.611 ;
     RECT  46.752 0.016 48.504 0.611 ;
     RECT  52.224 0.016 53.976 0.611 ;
     RECT  54.96 0.016 56.76 0.611 ;
     RECT  57.744 0.016 60.456 0.611 ;
     RECT  23.52 0.016 24.12 1.763 ;
     RECT  41.808 0.611 41.832 1.763 ;
     RECT  44.016 0.611 45.192 1.763 ;
     RECT  49.488 0.016 51.24 1.763 ;
     RECT  52.8 0.611 53.976 1.763 ;
     RECT  55.536 0.611 56.76 1.763 ;
     RECT  58.32 0.611 58.344 1.763 ;
     RECT  59.472 0.611 59.496 1.763 ;
     RECT  31.92 0.131 31.944 2.137 ;
     RECT  43.008 0.611 43.032 2.137 ;
     RECT  2.4 2.137 2.52 2.151 ;
     RECT  5.1 2.137 5.22 2.151 ;
     RECT  7.8 2.137 7.92 2.151 ;
     RECT  10.5 2.137 10.62 2.151 ;
     RECT  13.2 2.137 13.32 2.151 ;
     RECT  15.9 2.137 16.02 2.151 ;
     RECT  18.6 2.137 18.72 2.151 ;
     RECT  21.3 2.137 21.42 2.151 ;
     RECT  24 1.763 24.12 2.151 ;
     RECT  26.7 2.137 26.82 2.151 ;
     RECT  29.4 2.137 29.52 2.151 ;
     RECT  31.92 2.137 32.22 2.151 ;
     RECT  34.8 2.137 34.92 2.151 ;
     RECT  37.5 2.137 37.62 2.151 ;
     RECT  40.2 2.137 40.32 2.151 ;
     RECT  42.9 2.137 43.032 2.151 ;
     RECT  45.6 2.137 45.72 2.151 ;
     RECT  48.3 2.137 48.42 2.151 ;
     RECT  51 1.763 51.24 2.151 ;
     RECT  53.7 1.763 53.976 2.151 ;
     RECT  61.8 2.137 61.92 2.151 ;
     RECT  45.6 2.151 45.912 3.157 ;
     RECT  29.4 2.151 29.712 3.301 ;
     RECT  53.7 2.151 54.012 3.349 ;
     RECT  7.8 2.151 8.112 3.637 ;
     RECT  59.1 2.137 59.412 3.685 ;
     RECT  18.6 2.151 18.912 3.829 ;
     RECT  56.4 1.763 56.712 3.925 ;
     RECT  44.64 3.157 45.912 4.163 ;
     RECT  53.04 3.349 54.012 4.259 ;
     RECT  55.824 3.925 56.712 4.259 ;
     RECT  57.696 3.157 57.72 4.259 ;
     RECT  58.704 3.685 59.412 4.259 ;
     RECT  24 2.151 24.312 4.501 ;
     RECT  2.4 2.151 2.712 7.909 ;
     RECT  2.4 7.909 3.288 7.957 ;
     RECT  5.1 2.151 5.412 7.957 ;
     RECT  7.8 3.637 8.808 8.147 ;
     RECT  6.528 8.149 6.552 8.485 ;
     RECT  7.8 8.147 8.112 8.485 ;
     RECT  2.4 7.957 5.412 9.107 ;
     RECT  6.528 8.485 8.112 9.925 ;
     RECT  6.384 9.925 8.112 10.883 ;
     RECT  4.176 9.107 5.412 10.933 ;
     RECT  6.384 10.883 6.552 10.933 ;
     RECT  2.4 9.107 2.712 14.197 ;
     RECT  4.176 10.933 6.552 14.197 ;
     RECT  7.8 10.883 8.112 14.197 ;
     RECT  2.4 14.197 6.552 15.349 ;
     RECT  7.8 14.197 8.232 16.261 ;
     RECT  10.5 2.151 10.812 16.501 ;
     RECT  48.3 2.151 48.612 16.501 ;
     RECT  48.192 16.501 48.612 17.317 ;
     RECT  42.9 2.151 43.212 17.605 ;
     RECT  2.4 15.349 6.648 17.651 ;
     RECT  40.2 2.151 40.512 17.653 ;
     RECT  13.2 2.151 13.512 17.701 ;
     RECT  48.192 17.317 49.368 17.893 ;
     RECT  39.792 17.653 40.512 17.941 ;
     RECT  42.9 17.605 43.896 17.941 ;
     RECT  45.6 4.163 45.912 18.133 ;
     RECT  46.896 17.893 46.92 18.133 ;
     RECT  39.792 17.941 43.896 18.275 ;
     RECT  13.2 17.701 14.472 18.419 ;
     RECT  48.048 17.893 49.368 18.421 ;
     RECT  51 2.151 51.312 18.421 ;
     RECT  45.6 18.133 46.92 18.709 ;
     RECT  10.368 16.501 10.812 18.947 ;
     RECT  17.904 3.829 18.912 19.093 ;
     RECT  45.6 18.709 47.016 19.237 ;
     RECT  37.5 2.151 37.812 19.333 ;
     RECT  12 18.757 12.024 19.667 ;
     RECT  45.312 19.237 47.016 19.909 ;
     RECT  39.792 18.275 43.212 20.053 ;
     RECT  44.736 19.909 47.016 20.053 ;
     RECT  15.9 2.151 16.212 20.149 ;
     RECT  17.664 19.093 18.912 20.149 ;
     RECT  37.5 19.333 38.328 20.245 ;
     RECT  39.792 20.053 47.016 20.389 ;
     RECT  39.6 20.389 47.016 20.533 ;
     RECT  55.152 4.501 55.176 20.677 ;
     RECT  56.4 4.259 56.712 20.677 ;
     RECT  39.456 20.533 47.016 20.725 ;
     RECT  48.048 18.421 51.312 20.725 ;
     RECT  10.5 18.947 10.812 20.773 ;
     RECT  37.344 20.245 38.328 20.965 ;
     RECT  39.456 20.725 51.312 20.965 ;
     RECT  37.344 20.965 51.312 21.109 ;
     RECT  10.368 20.773 10.812 21.155 ;
     RECT  37.344 21.109 51.528 21.157 ;
     RECT  37.152 21.157 51.528 21.205 ;
     RECT  15.9 20.149 18.912 21.251 ;
     RECT  37.056 21.205 51.624 21.491 ;
     RECT  2.4 17.651 6.408 21.541 ;
     RECT  29.4 3.301 30.504 21.637 ;
     RECT  34.8 2.151 35.112 21.637 ;
     RECT  24 4.501 25.224 21.683 ;
     RECT  37.5 21.491 51.624 21.733 ;
     RECT  53.7 4.259 54.012 21.925 ;
     RECT  37.5 21.733 51.864 21.971 ;
     RECT  53.376 21.925 54.012 22.069 ;
     RECT  15.9 21.251 16.344 22.355 ;
     RECT  55.152 20.677 56.712 22.451 ;
     RECT  37.5 21.971 51.816 22.501 ;
     RECT  52.896 22.069 54.012 22.549 ;
     RECT  2.4 21.541 6.744 22.741 ;
     RECT  7.8 16.261 8.76 22.741 ;
     RECT  21.3 2.151 21.612 22.741 ;
     RECT  37.392 22.501 51.816 22.741 ;
     RECT  37.056 22.741 51.816 22.789 ;
     RECT  31.92 2.151 32.412 23.029 ;
     RECT  36.576 22.789 51.816 23.075 ;
     RECT  37.392 23.075 51.816 23.077 ;
     RECT  52.848 22.549 54.012 23.077 ;
     RECT  34.8 21.637 35.256 23.123 ;
     RECT  37.392 23.077 54.012 23.317 ;
     RECT  20.064 21.013 20.088 23.363 ;
     RECT  21.3 22.741 22.056 23.363 ;
     RECT  56.4 22.451 56.712 23.893 ;
     RECT  29.4 21.637 30.552 23.987 ;
     RECT  37.392 23.317 54.168 24.229 ;
     RECT  55.152 22.451 55.176 24.229 ;
     RECT  29.4 23.987 30.36 24.563 ;
     RECT  24 21.683 24.312 24.613 ;
     RECT  37.392 24.229 55.176 24.661 ;
     RECT  10.5 21.155 10.812 24.949 ;
     RECT  11.952 24.469 11.976 24.949 ;
     RECT  13.2 18.419 13.512 24.949 ;
     RECT  26.7 2.151 27.012 24.949 ;
     RECT  34.8 23.123 35.112 24.949 ;
     RECT  37.056 24.661 55.176 25.043 ;
     RECT  21.3 23.363 21.612 25.045 ;
     RECT  10.5 24.949 11.976 25.187 ;
     RECT  37.104 25.043 55.176 25.187 ;
     RECT  2.4 22.741 8.76 25.669 ;
     RECT  31.92 23.029 33.096 25.717 ;
     RECT  10.5 25.187 11.592 25.763 ;
     RECT  29.4 24.563 30.264 25.763 ;
     RECT  20.544 25.045 21.612 25.955 ;
     RECT  23.712 24.613 24.312 26.005 ;
     RECT  31.824 25.717 33.096 26.005 ;
     RECT  56.4 23.893 57.288 26.053 ;
     RECT  31.824 26.005 33.288 26.101 ;
     RECT  34.8 24.949 35.88 26.101 ;
     RECT  31.824 26.101 35.88 26.197 ;
     RECT  26.592 24.949 27.012 26.243 ;
     RECT  31.296 26.197 35.88 26.291 ;
     RECT  10.5 25.763 11.544 26.293 ;
     RECT  23.136 26.005 24.312 26.293 ;
     RECT  17.472 21.251 18.912 26.387 ;
     RECT  23.136 26.293 24.792 26.437 ;
     RECT  37.104 25.187 54.168 26.629 ;
     RECT  55.152 25.187 55.176 26.629 ;
     RECT  31.296 26.291 33.72 26.675 ;
     RECT  37.104 26.629 55.176 26.675 ;
     RECT  31.296 26.675 33.288 26.723 ;
     RECT  2.4 25.669 8.808 26.725 ;
     RECT  23.088 26.437 24.792 26.725 ;
     RECT  2.4 26.725 8.856 26.869 ;
     RECT  37.104 26.675 54.984 27.109 ;
     RECT  37.056 27.109 54.984 27.251 ;
     RECT  15.9 22.355 16.212 27.301 ;
     RECT  56.4 26.053 57.336 27.395 ;
     RECT  37.104 27.251 54.984 27.539 ;
     RECT  29.4 25.763 29.712 27.877 ;
     RECT  13.2 24.949 13.656 27.925 ;
     RECT  10.368 26.293 11.544 27.971 ;
     RECT  17.664 26.387 18.912 27.973 ;
     RECT  29.088 27.877 29.712 28.021 ;
     RECT  15.36 27.301 16.212 28.451 ;
     RECT  13.104 27.925 13.656 28.499 ;
     RECT  29.088 28.021 29.928 28.499 ;
     RECT  22.896 26.725 24.792 28.739 ;
     RECT  31.296 26.723 33.144 28.835 ;
     RECT  26.7 26.243 27.012 28.981 ;
     RECT  17.664 27.973 19.848 29.029 ;
     RECT  21.3 25.955 21.612 29.029 ;
     RECT  34.8 26.291 35.88 29.029 ;
     RECT  37.5 27.539 54.984 29.029 ;
     RECT  56.4 27.395 56.712 29.029 ;
     RECT  29.088 28.499 29.832 29.075 ;
     RECT  31.92 28.835 33.144 29.075 ;
     RECT  34.8 29.029 35.976 29.077 ;
     RECT  37.5 29.029 56.712 29.077 ;
     RECT  23.232 28.739 24.792 29.171 ;
     RECT  26.7 28.981 27.24 29.173 ;
     RECT  25.776 29.173 27.24 29.315 ;
     RECT  34.8 29.077 56.712 29.651 ;
     RECT  17.664 29.029 21.612 29.699 ;
     RECT  25.776 29.315 27.012 29.843 ;
     RECT  23.328 29.171 24.792 30.133 ;
     RECT  59.1 4.259 59.412 30.133 ;
     RECT  29.088 29.075 29.712 30.469 ;
     RECT  28.32 30.469 29.712 30.853 ;
     RECT  28.128 30.853 29.712 30.995 ;
     RECT  28.608 30.995 29.712 31.091 ;
     RECT  56.4 29.651 56.712 31.669 ;
     RECT  34.8 29.651 55.128 31.715 ;
     RECT  58.896 30.133 59.412 31.811 ;
     RECT  17.664 29.699 19.848 31.859 ;
     RECT  15.9 28.451 16.212 31.861 ;
     RECT  18.24 31.859 19.848 31.955 ;
     RECT  23.28 30.133 24.792 32.293 ;
     RECT  32.1 29.075 33.144 32.437 ;
     RECT  2.4 26.869 9.144 32.821 ;
     RECT  10.368 27.971 10.812 32.821 ;
     RECT  34.8 31.715 54.12 32.965 ;
     RECT  55.104 31.715 55.128 32.965 ;
     RECT  32.1 32.437 33.192 33.011 ;
     RECT  21.3 29.699 21.612 33.013 ;
     RECT  22.8 32.293 24.792 33.155 ;
     RECT  18.24 31.955 18.912 33.683 ;
     RECT  34.8 32.965 55.128 33.683 ;
     RECT  26.7 29.843 27.012 33.829 ;
     RECT  20.544 33.013 21.612 34.115 ;
     RECT  13.2 28.499 13.656 34.117 ;
     RECT  29.4 31.091 29.712 34.789 ;
     RECT  22.8 33.155 24.408 34.933 ;
     RECT  29.04 34.789 29.712 35.027 ;
     RECT  34.8 33.683 54.936 35.219 ;
     RECT  12.528 34.117 13.656 35.363 ;
     RECT  20.256 34.741 20.28 35.459 ;
     RECT  32.1 33.011 33.144 35.459 ;
     RECT  22.8 34.933 25.272 35.555 ;
     RECT  26.7 33.829 27.912 35.891 ;
     RECT  22.8 35.555 22.968 36.035 ;
     RECT  24 35.555 25.272 36.037 ;
     RECT  15.9 31.861 17.016 36.275 ;
     RECT  13.2 35.363 13.656 36.469 ;
     RECT  56.4 31.669 56.808 36.469 ;
     RECT  26.7 35.891 27.816 37.043 ;
     RECT  2.4 32.821 10.812 37.091 ;
     RECT  22.8 36.035 22.824 37.091 ;
     RECT  21.3 34.115 21.612 37.285 ;
     RECT  13.104 36.469 13.656 37.379 ;
     RECT  34.8 35.219 54.12 37.715 ;
     RECT  15.9 36.275 16.344 37.907 ;
     RECT  56.4 36.469 57 37.955 ;
     RECT  56.4 37.955 56.808 38.195 ;
     RECT  2.4 37.091 9.48 38.435 ;
     RECT  13.2 37.379 13.656 38.581 ;
     RECT  21.168 37.285 21.612 38.629 ;
     RECT  24 36.037 25.32 38.725 ;
     RECT  26.7 37.043 27.012 38.725 ;
     RECT  12.24 38.581 13.656 38.819 ;
     RECT  39.168 37.715 54.12 38.819 ;
     RECT  24 38.725 27.012 38.963 ;
     RECT  42.48 38.819 54.12 39.107 ;
     RECT  26.064 38.963 27.012 39.157 ;
     RECT  24 38.963 24.552 39.251 ;
     RECT  44.448 39.107 54.12 39.299 ;
     RECT  40.2 38.819 41.16 39.347 ;
     RECT  26.064 39.157 27.768 39.395 ;
     RECT  49.92 39.299 54.12 39.443 ;
     RECT  42.48 39.107 43.32 39.587 ;
     RECT  42.672 39.587 43.32 39.731 ;
     RECT  42.9 39.731 43.32 39.827 ;
     RECT  34.8 37.715 37.812 39.923 ;
     RECT  44.448 39.299 48.936 39.923 ;
     RECT  20.544 38.629 21.612 40.019 ;
     RECT  39.168 38.819 39.192 40.021 ;
     RECT  40.2 39.347 41.112 40.021 ;
     RECT  34.8 39.923 35.976 40.067 ;
     RECT  44.448 39.923 47.16 40.163 ;
     RECT  48.3 39.923 48.936 40.357 ;
     RECT  39.168 40.021 41.112 40.451 ;
     RECT  48.3 40.357 49.032 40.499 ;
     RECT  50.4 39.443 54.12 40.499 ;
     RECT  51 40.499 54.12 40.547 ;
     RECT  34.8 40.067 35.688 40.691 ;
     RECT  52.848 40.547 54.12 40.835 ;
     RECT  42.9 39.827 43.212 40.837 ;
     RECT  38.976 40.453 39 40.979 ;
     RECT  12.24 38.819 13.512 40.981 ;
     RECT  42.9 40.837 43.992 40.981 ;
     RECT  20.928 40.019 21.612 41.027 ;
     RECT  51 40.547 51.864 41.075 ;
     RECT  12.24 40.981 13.8 41.123 ;
     RECT  42.768 40.981 43.992 41.171 ;
     RECT  44.976 40.163 47.16 41.317 ;
     RECT  44.832 41.317 47.16 41.459 ;
     RECT  53.7 40.835 54.12 41.459 ;
     RECT  26.064 39.395 27.012 41.651 ;
     RECT  40.2 40.451 41.112 41.651 ;
     RECT  21.168 41.027 21.612 41.699 ;
     RECT  42.768 41.171 43.212 41.747 ;
     RECT  15.9 37.907 16.212 41.941 ;
     RECT  45.456 41.459 47.16 42.227 ;
     RECT  45.456 42.227 46.872 42.275 ;
     RECT  14.832 33.253 14.856 42.323 ;
     RECT  40.2 41.651 40.872 42.755 ;
     RECT  45.504 42.275 46.872 42.755 ;
     RECT  12 41.557 12.024 42.851 ;
     RECT  13.2 41.123 13.8 43.379 ;
     RECT  13.2 43.379 13.512 44.437 ;
     RECT  15.9 41.941 16.536 44.675 ;
     RECT  13.056 44.437 13.512 45.155 ;
     RECT  2.4 38.435 9.144 46.499 ;
     RECT  3.888 46.499 9.144 50.771 ;
     RECT  4.896 50.771 8.568 51.347 ;
     RECT  3.888 50.771 3.912 54.179 ;
     RECT  5.1 51.347 8.568 54.179 ;
     RECT  6.576 54.179 8.568 54.755 ;
     RECT  6.72 54.755 6.744 55.283 ;
     RECT  5.1 54.179 5.544 55.331 ;
     RECT  7.8 54.755 8.568 56.003 ;
     RECT  2.4 46.499 2.712 62.649 ;
     RECT  5.1 55.331 5.412 62.649 ;
     RECT  7.8 56.003 8.112 62.649 ;
     RECT  10.5 37.091 10.812 62.649 ;
     RECT  13.2 45.155 13.512 62.649 ;
     RECT  15.9 44.675 16.212 62.649 ;
     RECT  18.6 33.683 18.912 62.649 ;
     RECT  21.3 41.699 21.612 62.649 ;
     RECT  24 39.251 24.312 62.649 ;
     RECT  26.7 41.651 27.012 62.649 ;
     RECT  29.4 35.027 29.712 62.649 ;
     RECT  32.1 35.459 32.412 62.649 ;
     RECT  34.8 40.691 35.112 62.649 ;
     RECT  37.5 39.923 37.812 62.649 ;
     RECT  40.2 42.755 40.512 62.649 ;
     RECT  42.9 41.747 43.212 62.649 ;
     RECT  45.6 42.755 45.912 62.649 ;
     RECT  48.3 40.499 48.612 62.649 ;
     RECT  51 41.075 51.312 62.649 ;
     RECT  53.7 41.459 54.012 62.649 ;
     RECT  56.4 38.195 56.712 62.649 ;
     RECT  59.1 31.811 59.412 62.649 ;
     RECT  61.8 2.151 62.112 62.649 ;
     RECT  2.4 62.649 2.52 62.663 ;
     RECT  5.1 62.649 5.22 62.663 ;
     RECT  7.8 62.649 7.92 62.663 ;
     RECT  10.5 62.649 10.62 62.663 ;
     RECT  13.2 62.649 13.32 62.663 ;
     RECT  15.9 62.649 16.02 62.663 ;
     RECT  18.6 62.649 18.72 62.663 ;
     RECT  21.3 62.649 21.42 62.663 ;
     RECT  24 62.649 24.12 62.663 ;
     RECT  26.7 62.649 26.82 62.663 ;
     RECT  29.4 62.649 29.52 62.663 ;
     RECT  32.1 62.649 32.22 62.663 ;
     RECT  34.8 62.649 34.92 62.663 ;
     RECT  37.5 62.649 37.62 62.663 ;
     RECT  40.2 62.649 40.32 62.663 ;
     RECT  42.9 62.649 43.02 62.663 ;
     RECT  45.6 62.649 45.72 62.663 ;
     RECT  48.3 62.649 48.42 62.663 ;
     RECT  51 62.649 51.12 62.663 ;
     RECT  53.7 62.649 53.82 62.663 ;
     RECT  56.4 62.649 56.52 62.663 ;
     RECT  59.1 62.649 59.22 62.663 ;
     RECT  61.8 62.649 61.92 62.663 ;
  END
END qvm_return_plane_pin_native
END LIBRARY
